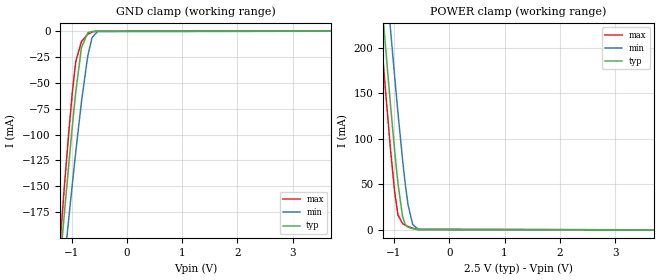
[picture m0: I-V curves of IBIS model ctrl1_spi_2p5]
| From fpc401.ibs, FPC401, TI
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|   ctrl1_spi_2p5 Model
[Model]   ctrl1_spi_2p5
Model_type   Input
Vinl = 0.75
Vinh = 1.75
|   typ   min   max
|   (nom PVT)   (fast PVT)   (slow PVT)
C_comp   3.323e-12   3.283e-12   3.373e-12
| Where nom  PVT is Nominal Process, 2.5V, 27C
|   Fast PVT is Strong Process,  2.65V, -40C
|   Slow PVT is Weak Process,   2.35V, 125C
[Voltage Range]   2.5   2.35   2.65
|Junction Temperature
[Temperature Range]   27   125   -40
[Power Clamp Reference]   2.5   2.35   2.65
[GND Clamp Reference]   0   0   0
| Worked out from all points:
|   GND clamp passes 1 mA (typ) near -0.67 V on its own axis
|   POWER clamp passes 1 mA (typ) near -0.63 V on its own axis
[GND Clamp]
|   Voltage   I(typ)   I(min)   I(max)
-2.5V     -1.076A    -999.1mA   -1.173A
-1.265V   -260.4mA   -296.2mA   -245.6mA
-1.133V   -178.4mA   -224.7mA   -152.9mA
-1.097V   -157mA     -205.9mA   -129mA
-1.052V   -130.5mA   -182.5mA   -99.78mA
-985mV    -91.97mA   -147.8mA   -58.97mA
-923.2mV  -58.98mA   -116.9mA   -29.3mA
-819.9mV  -15.92mA   -68.35mA   -10.12mA
-705.9mV  -1.65mA    -24.05mA   -3.017mA
-627.5mV  -378.3uA   -6.231mA   -803.9uA
-530.7mV  -48.81uA   -526.9uA   -88.92uA
5V        0A         0A         0A
[POWER Clamp]
|   Voltage   I(typ)   I(min)   I(max)
-2.5V     1.257A     1.315A     1.24A
-1.26V    279.7mA    361.8mA    232.8mA
-1.159V   205.3mA    288.3mA    156.9mA
-1.062V   136.2mA    219.1mA    87.67mA
-987.5mV  86.55mA    167.9mA    41.5mA
-928.5mV  51.09mA    128.7mA    16.6mA
-845.6mV  14.85mA    77.42mA    7.025mA
-793.9mV  5.674mA    49.25mA    5.223mA
-745.7mV  3.042mA    27.55mA    3.847mA
-662.3mV  1.416mA    6.079mA    1.934mA
-563.6mV  434.9uA    773.4uA    531.7uA
5V        0A         0A         0A
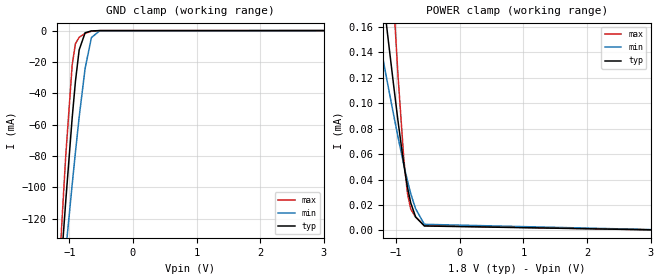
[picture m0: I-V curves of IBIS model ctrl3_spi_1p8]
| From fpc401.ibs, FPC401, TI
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|   ctrl3_spi_1p8 Model
[Model]   ctrl3_spi_1p8
Model_type   Input
Vinl = 0.54
Vinh = 1.26
|   typ   min   max
|   (nom PVT)   (fast PVT)   (slow PVT)
C_comp   1.078e-12   1.078e-12   1.078e-12
| Where nom  PVT is Nominal Process, 1.8V, 27C
|   Fast PVT is Strong Process,  1.95V, -40C
|   Slow PVT is Weak Process,   1.65V, 125C
[Voltage Range]   1.8   1.65   1.95
|Junction Temperature
[Temperature Range]   27   125   -40
[Power Clamp Reference]   1.8   1.65   1.95
[GND Clamp Reference]   0   0   0
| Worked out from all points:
|   GND clamp passes 1 mA (typ) near -0.73 V on its own axis
[GND Clamp]
|   Voltage   I(typ)   I(min)   I(max)
-1.8V     -556.9mA   -476.6mA   -661.8mA
-1.191V   -186.6mA   -199.8mA   -178.6mA
-1.147V   -160.7mA   -180.3mA   -145.3mA
-1.108V   -138.4mA   -163.3mA   -116.8mA
-1.055V   -108.6mA   -140.4mA   -79.7mA
-953.7mV  -55.51mA   -98.01mA   -21.81mA
-903mV    -32.44mA   -77.62mA   -8.4mA
-844.2mV  -12.32mA   -55.13mA   -4.254mA
-750.6mV  -1.393mA   -24.05mA   -1.808mA
-651.6mV  -214.4uA   -4.491mA   -445.5uA
-522.9mV  -14.93uA   -149.5uA   -26.3uA
3.6V      0A         0A         0A
[POWER Clamp]
|   Voltage   I(typ)   I(min)   I(max)
-1.8V     453.3uA    299uA      889.9uA
-1.401V   271.5uA    187.6uA    509.9uA
-1.256V   207.1uA    148.1uA    374.7uA
-1.135V   154.4uA    115.7uA    264.1uA
-1.041V   114.8uA    91.31uA    181.3uA
-969.3mV  85.51uA    73.08uA    120.8uA
-878.4mV  51.63uA    51.35uA    55.59uA
-822.6mV  34.16uA    39.13uA    29.31uA
-770.4mV  21.71uA    28.95uA    16.82uA
-694.8mV  10.77uA    17.16uA    10.5uA
-556.2mV  3.534uA    4.838uA    3.853uA
3.6V      0A         0A         0A
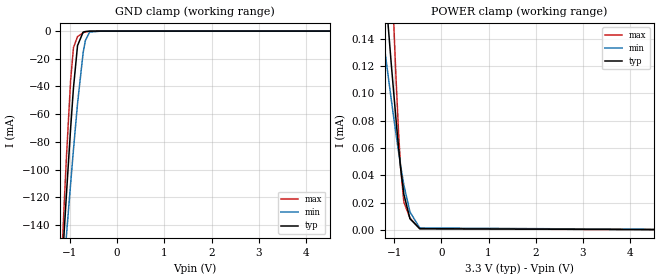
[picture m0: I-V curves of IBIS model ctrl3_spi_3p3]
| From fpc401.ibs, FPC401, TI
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|   ctrl3_spi_3p3 Model
[Model]   ctrl3_spi_3p3
Model_type   Input
Vinl = 0.99
Vinh = 2.31
|   typ   min   max
|   (nom PVT)   (fast PVT)   (slow PVT)
C_comp   1.079e-12   1.078e-12   1.087e-12
| Where nom  PVT is Nominal Process, 3.3V, 27C
|   Fast PVT is Strong Process,  3.6V, -40C
|   Slow PVT is Weak Process,   3V, 125C
[Voltage Range]   3.3   3   3.6
|Junction Temperature
[Temperature Range]   27   125   -40
[Power Clamp Reference]   3.3   3   3.6
[GND Clamp Reference]   0   0   0
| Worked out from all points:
|   GND clamp passes 1 mA (typ) near -0.73 V on its own axis
[GND Clamp]
|   Voltage   I(typ)   I(min)   I(max)
-3.3V     -1.497A    -1.178A    -1.889A
-1.197V   -189.1mA   -201.8mA   -181.8mA
-1.115V   -141.5mA   -165.7mA   -120.7mA
-1.076V   -119.5mA   -148.9mA   -92.97mA
-985.2mV  -70.57mA   -110.5mA   -35.84mA
-924mV    -40.87mA   -85.43mA   -11.9mA
-838.2mV  -10.51mA   -52.44mA   -3.986mA
-720mV    -732.9uA   -15.76mA   -1.234mA
-672mV    -304.1uA   -6.775mA   -613.8uA
-582mV    -52.5uA    -738.5uA   -104.3uA
-330mV    -89.36nA   -744.8nA   -56.52nA
6.6V      0A         0A         0A
[POWER Clamp]
|   Voltage   I(typ)   I(min)   I(max)
-3.3V     1.156mA    727.3uA    2.344mA
-1.251V   204.1uA    146.3uA    368.3uA
-1.2V     181.9uA    132.7uA    321.6uA
-1.082V   131.3uA    101.5uA    215.6uA
-1.061V   122.2uA    95.94uA    196.6uA
-960mV    81.27uA    70.45uA    112.1uA
-906mV    60.85uA    57.44uA    72.14uA
-862.8mV  45.91uA    47.53uA    45.99uA
-792mV    26uA       32.73uA    20.37uA
-663.3mV  8.201uA    13.21uA    8.723uA
-456mV    938.5nA    1.48uA     846.4nA
6.6V      0A         0A         0A
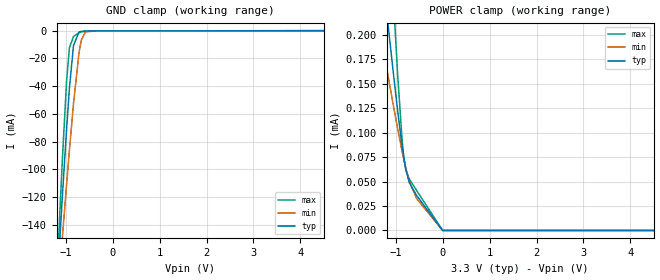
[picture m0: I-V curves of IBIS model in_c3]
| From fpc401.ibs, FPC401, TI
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|   in_c3 Model
[Model]   in_c3
Model_type   Input
Vinl = 0.8
Vinh = 2
|   typ   min   max
|   (nom PVT)   (fast PVT)   (slow PVT)
C_comp   1.056e-12   1.054e-12   1.064e-12
| Where nom  PVT is Nominal Process, 3.3V, 27C
|   Fast PVT is Strong Process,  3.6V, -40C
|   Slow PVT is Weak Process,   3V, 125C
[Voltage Range]   3.3   3   3.6
|Junction Temperature
[Temperature Range]   27   125   -40
[Power Clamp Reference]   3.3   3   3.6
[GND Clamp Reference]   0   0   0
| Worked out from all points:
|   GND clamp passes 1 mA (typ) near -0.72 V on its own axis
[GND Clamp]
|   Voltage   I(typ)   I(min)   I(max)
-3.3V     -1.497A    -1.178A    -1.889A
-1.197V   -189.4mA   -202mA     -182.1mA
-1.115V   -141.8mA   -166mA     -121mA
-1.076V   -119.7mA   -149.1mA   -93.29mA
-985.2mV  -70.83mA   -110.7mA   -36.16mA
-924mV    -41.13mA   -85.64mA   -12.21mA
-838.2mV  -10.77mA   -52.65mA   -4.3mA
-720mV    -986.9uA   -15.96mA   -1.546mA
-672mV    -556.6uA   -6.981mA   -923.9uA
-582mV    -301.4uA   -942.3uA   -410.8uA
-330mV    -233.9uA   -192uA     -289.6uA
6.6V      0A         0A         0A
[POWER Clamp]
|   Voltage   I(typ)   I(min)   I(max)
-3.3V     1.207mA    765.2uA    2.408mA
-1.37V    301.9uA    213.7uA    529.6uA
-1.188V   219.4uA    163.6uA    358.5uA
-1.056V   161.5uA    128.2uA    238.7uA
-960mV    121.3uA    103.4uA    157.2uA
-864.6mV  85.16uA    80.14uA    90.59uA
-826.8mV  72.99uA    71.6uA     73.26uA
-786mV    62.04uA    63.05uA    61.53uA
-715.2mV  48.87uA    50.4uA     52.66uA
-558mV    35.78uA    32.63uA    40.88uA
-3.3mV    0A         17.47nA    44.25nA
6.6V      0A         0A         0A
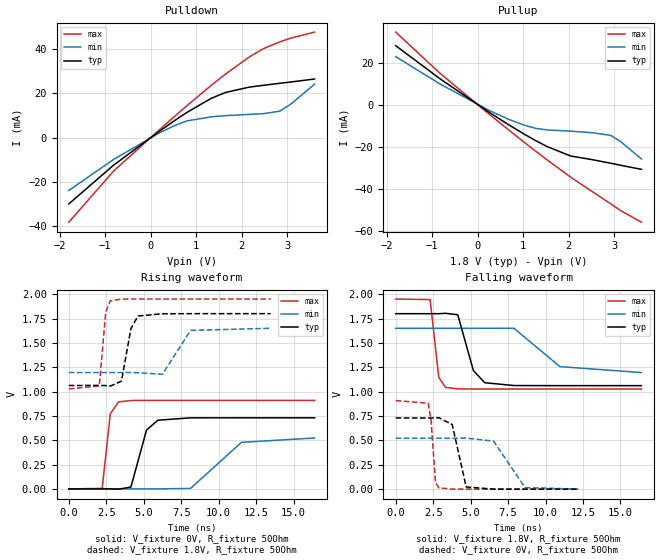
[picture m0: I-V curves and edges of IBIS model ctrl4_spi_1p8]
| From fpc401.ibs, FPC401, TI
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|   ctrl4_spi_1p8 Model
[Model]   ctrl4_spi_1p8
Model_type   Output
Polarity   Non-Inverting
Vmeas = 0.9
Vref = 0
Cref = 2pF
Rref =150
|   typ   min   max
|   (nom PVT)   (fast PVT)   (slow PVT)
C_comp   1.266e-14   1.230e-14   1.995e-14
| Where nom  PVT is Nominal Process, 1.8V, 27C
|   Fast PVT is Strong Process,  1.95V, -40C
|   Slow PVT is Weak Process,   1.65V, 125C
[Voltage Range]   1.8   1.65   1.95
|Junction Temperature
[Temperature Range]   27   125   -40
[Pullup Reference]   1.8   1.65   1.95
[Pulldown Reference]   0   0   0
[Power Clamp Reference]   1.8   1.65   1.95
[GND Clamp Reference]   0   0   0
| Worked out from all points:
|   slope of the pulldown table from 0 to 0.27 V, typ, clamps not added: 67.3 ohm
|   slope of the pullup table from 0 to 0.27 V, typ, clamps not added: 69.9 ohm
|   falling waveform, V_fixture 1.8V, R_fixture 50Ohm: 20-80 % time 784ps typ, 1.97ns min, 310ps max; typ from 1.8 V to 1.06 V
|   rising waveform, V_fixture 0V, R_fixture 50Ohm: 20-80 % time 722ps typ, 1.87ns min, 319ps max; typ from 0 V to 0.73 V
|   rising waveform, V_fixture 1.8V, R_fixture 50Ohm: 20-80 % time 468ps typ, 792ps min, 241ps max; typ from 1.06 V to 1.8 V
|   falling waveform, V_fixture 0V, R_fixture 50Ohm: 20-80 % time 510ps typ, 1.11ns min, 236ps max; typ from 0.73 V to 0 V
[Pulldown]
|   Voltage   I(typ)   I(min)   I(max)
-1.8V     -30.03mA   -23.95mA   -38.3mA
-817.2mV  -12.51mA   -9.904mA   -15.17mA
196.8mV   2.965mA    2.195mA    3.659mA
528.2mV   7.741mA    5.468mA    9.674mA
795.4mV   11.39mA    7.539mA    14.44mA
1.328V    17.75mA    9.395mA    23.6mA
1.649V    20.46mA    9.924mA    28.84mA
2.166V    22.83mA    10.5mA     36.51mA
2.482V    23.67mA    10.84mA    40.31mA
2.835V    24.57mA    11.94mA    43.31mA
3.089V    25.18mA    15.32mA    45.08mA
3.6V      26.51mA    24.19mA    47.74mA
[Pullup]
|   Voltage   I(typ)   I(min)   I(max)
-1.8V     28.02mA    22.83mA    34.49mA
-822.6mV  12.23mA    9.767mA    14.82mA
251mV     -3.622mA   -2.739mA   -4.498mA
671.7mV   -9.444mA   -6.899mA   -11.87mA
1.024V    -14.05mA   -9.784mA   -17.92mA
1.287V    -17.27mA   -11.33mA   -22.35mA
1.533V    -20.03mA   -12.06mA   -26.4mA
2.045V    -24.44mA   -12.63mA   -34.5mA
2.524V    -26.21mA   -13.38mA   -41.45mA
2.929V    -27.91mA   -14.69mA   -47.25mA
3.147V    -28.88mA   -17.66mA   -50.48mA
3.6V      -30.8mA    -25.87mA   -55.93mA
[Ramp]
R_load = 50
|   typ   min   max
dV/dt_r   0.438136/7.21814e-10   0.313826/1.87407e-09   0.545381/3.19219e-10
dV/dt_f   0.442539/7.83738e-10   0.273051/1.97718e-09   0.553614/3.09688e-10
[Falling Waveform]
V_fixture = 1.8V
V_fixture_min = 1.65V
V_fixture_max = 1.95V
R_fixture = 50Ohm
|   Time   V(typ)   V(min)   V(max)
0s        1.8V       1.65V      1.95V
2.294ns   1.8V       1.65V      1.945V
2.875ns   1.8V       1.65V      1.148V
3.319ns   1.804V     1.65V      1.044V
4.144ns   1.789V     1.65V      1.029V
5.185ns   1.217V     1.65V      1.027V
5.939ns   1.092V     1.651V     1.027V
7.886ns   1.063V     1.651V     1.027V
10.96ns   1.062V     1.257V     1.027V
16.4ns    1.062V     1.196V     1.027V
[Rising Waveform]
V_fixture = 0V
V_fixture_min = 0V
V_fixture_max = 0V
R_fixture = 50Ohm
|   Time   V(typ)   V(min)   V(max)
0s        523pV      20.8nV     260.9pV
2.227ns   90.6uV     12.08nV    5.005mV
2.767ns   259.2uV    10.87nV    771.4mV
3.319ns   -2.879mV   2.108uV    893.8mV
4.144ns   19.03mV    3.658uV    907.9mV
5.185ns   604.2mV    233.8uV    908.9mV
5.939ns   705.7mV    -162.1uV   909mV
8.124ns   729.8mV    5.132mV    909mV
11.52ns   730.2mV    478.2mV    909mV
16.4ns    730.2mV    522.8mV    909mV
[Rising Waveform]
V_fixture = 1.8V
V_fixture_min = 1.65V
V_fixture_max = 1.95V
R_fixture = 50Ohm
|   Time   V(typ)   V(min)   V(max)
0s        1.062V     1.195V     1.027V
2.033ns   1.063V     1.195V     1.058V
2.463ns   1.061V     1.195V     1.814V
2.767ns   1.056V     1.195V     1.933V
3.514ns   1.107V     1.195V     1.949V
4.144ns   1.646V     1.196V     1.95V
4.613ns   1.776V     1.193V     1.95V
6.242ns   1.799V     1.177V     1.95V
8.124ns   1.8V       1.628V     1.95V
13.47ns   1.8V       1.65V      1.95V
[Falling Waveform]
V_fixture = 0V
V_fixture_min = 0V
V_fixture_max = 0V
R_fixture = 50Ohm
|   Time   V(typ)   V(min)   V(max)
0s        730.2mV    523mV      909mV
2.168ns   730.1mV    523mV      881.3mV
2.355ns   730mV      523mV      713.7mV
2.657ns   731mV      523mV      70.24mV
2.875ns   732.7mV    523mV      13.61mV
3.771ns   662.9mV    522.8mV    299.2uV
4.705ns   22.74mV    523.5mV    12.73uV
6.531ns   304.9uV    493mV      1.942uV
8.628ns   9.883uV    16.63mV    -2.72uV
12.19ns   6.404uV    201uV      13.13uV
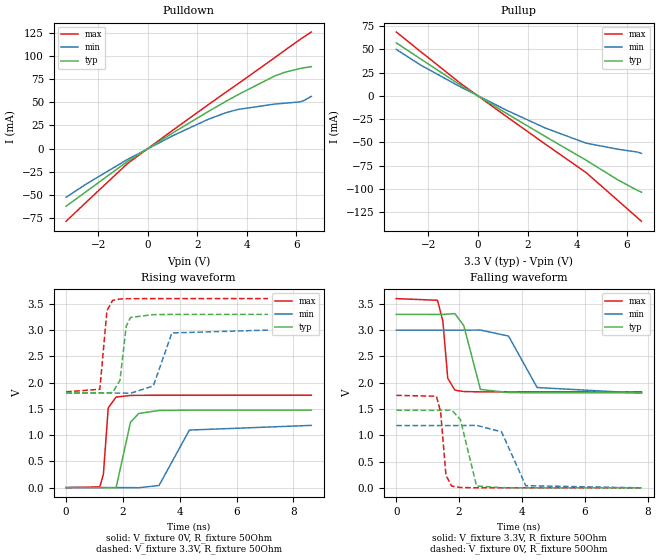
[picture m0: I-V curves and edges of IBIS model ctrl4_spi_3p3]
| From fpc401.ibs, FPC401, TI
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|   ctrl4_spi_3p3 Model
[Model]   ctrl4_spi_3p3
Model_type   Output
Polarity   Non-Inverting
Vmeas = 1.65
Vref = 0
Cref = 50pF
Rref = 100
|   typ   min   max
|   (nom PVT)   (fast PVT)   (slow PVT)
C_comp   1.230e-14   1.150e-14   1.962e-14
| Where nom  PVT is Nominal Process, 3.3V, 27C
|   Fast PVT is Strong Process,  3.6V, -40C
|   Slow PVT is Weak Process,   3V, 125C
[Voltage Range]   3.3   3   3.6
|Junction Temperature
[Temperature Range]   27   125   -40
[Pullup Reference]   3.3   3   3.6
[Pulldown Reference]   0   0   0
[Power Clamp Reference]   3.3   3   3.6
[GND Clamp Reference]   0   0   0
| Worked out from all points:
|   slope of the pulldown table from 0 to 0.495 V, typ, clamps not added: 59.6 ohm
|   slope of the pullup table from 0 to 0.495 V, typ, clamps not added: 61.1 ohm
|   falling waveform, V_fixture 3.3V, R_fixture 50Ohm: 20-80 % time 245ps typ, 505ps min, 153ps max; typ from 3.3 V to 1.81 V
|   rising waveform, V_fixture 0V, R_fixture 50Ohm: 20-80 % time 215ps typ, 511ps min, 127ps max; typ from 0 V to 1.48 V
|   rising waveform, V_fixture 3.3V, R_fixture 50Ohm: 20-80 % time 183ps typ, 339ps min, 124ps max; typ from 1.81 V to 3.3 V
|   falling waveform, V_fixture 0V, R_fixture 50Ohm: 20-80 % time 207ps typ, 367ps min, 137ps max; typ from 1.48 V to 0 V
[Pulldown]
|   Voltage   I(typ)   I(min)   I(max)
-3.3V     -62.26mA   -52.59mA   -78.49mA
-2.448V   -45.66mA   -37.66mA   -56.92mA
-822mV    -13.95mA   -11.79mA   -16.21mA
1.024V    17.12mA    14.05mA    20.07mA
2.436V    39.87mA    31.49mA    47.24mA
3.132V    50.59mA    38.48mA    60.38mA
3.63V     57.96mA    42.15mA    69.66mA
5.121V    78.27mA    47.97mA    98.01mA
5.554V    82.48mA    48.95mA    106.4mA
6.132V    86.26mA    50.27mA    117.4mA
6.316V    87.15mA    51.9mA     120.7mA
6.6V      88.32mA    56.28mA    125.7mA
[Pullup]
|   Voltage   I(typ)   I(min)   I(max)
-3.3V     57mA       49.97mA    68.61mA
-2.319V   39.75mA    33.18mA    47.64mA
-719.4mV  11.82mA    9.868mA    13.8mA
1.185V    -19.34mA   -15.77mA   -22.78mA
2.73V     -43.76mA   -34.6mA    -51.99mA
4.365V    -69.03mA   -50.72mA   -82.35mA
5.639V    -90.03mA   -57.17mA   -112.1mA
6.435V    -101.4mA   -60.27mA   -130.8mA
6.6V      -103.4mA   -61.66mA   -134.6mA
[Ramp]
R_load = 50
|   typ   min   max
dV/dt_r   0.88529/2.15442e-10   0.711024/5.10621e-10   1.05524/1.26841e-10
dV/dt_f   0.895288/2.4533e-10   0.719434/5.05804e-10   1.06478/1.53449e-10
[Falling Waveform]
V_fixture = 3.3V
V_fixture_min = 3V
V_fixture_max = 3.6V
R_fixture = 50Ohm
|   Time   V(typ)   V(min)   V(max)
0s        3.3V       3V         3.6V
1.313ns   3.299V     3V         3.568V
1.483ns   3.3V       3V         3.173V
1.639ns   3.305V     3V         2.085V
1.867ns   3.314V     3V         1.858V
2.15ns    3.085V     3V         1.832V
2.68ns    1.872V     3.002V     1.826V
3.576ns   1.812V     2.887V     1.825V
4.485ns   1.808V     1.908V     1.825V
7.808ns   1.808V     1.801V     1.825V
[Rising Waveform]
V_fixture = 0V
V_fixture_min = 0V
V_fixture_max = 0V
R_fixture = 50Ohm
|   Time   V(typ)   V(min)   V(max)
0s        657.7pV    14.65nV    458.6pV
1.188ns   507.5uV    36.28nV    16.22mV
1.313ns   422.5uV    1.028uV    253.9mV
1.483ns   -2.868mV   -3.276uV   1.52V
1.759ns   -4.429mV   20.3uV     1.724V
2.268ns   1.249V     354.1uV    1.756V
2.557ns   1.412V     -2.515mV   1.758V
3.271ns   1.469V     40.75mV    1.759V
4.338ns   1.475V     1.096V     1.759V
8.627ns   1.475V     1.185V     1.759V
[Rising Waveform]
V_fixture = 3.3V
V_fixture_min = 3V
V_fixture_max = 3.6V
R_fixture = 50Ohm
|   Time   V(typ)   V(min)   V(max)
0s        1.808V     1.801V     1.825V
1.188ns   1.808V     1.801V     1.873V
1.437ns   1.804V     1.801V     3.37V
1.639ns   1.812V     1.801V     3.567V
1.895ns   2.043V     1.801V     3.592V
2.117ns   3.075V     1.799V     3.598V
2.268ns   3.241V     1.797V     3.599V
3.069ns   3.295V     1.937V     3.6V
3.722ns   3.299V     2.946V     3.6V
7.105ns   3.3V       3V         3.6V
[Falling Waveform]
V_fixture = 0V
V_fixture_min = 0V
V_fixture_max = 0V
R_fixture = 50Ohm
|   Time   V(typ)   V(min)   V(max)
0s        1.476V     1.185V     1.759V
1.276ns   1.475V     1.185V     1.743V
1.412ns   1.476V     1.185V     1.448V
1.582ns   1.479V     1.185V     237.8mV
1.764ns   1.481V     1.185V     33mV
2.041ns   1.3V       1.185V     6.609mV
2.557ns   34.91mV    1.188V     531.1uV
3.351ns   3.222mV    1.066V     7.724uV
4.124ns   512.3uV    40.55mV    20.25uV
7.808ns   -13.34uV   266.7uV    -48.42uV
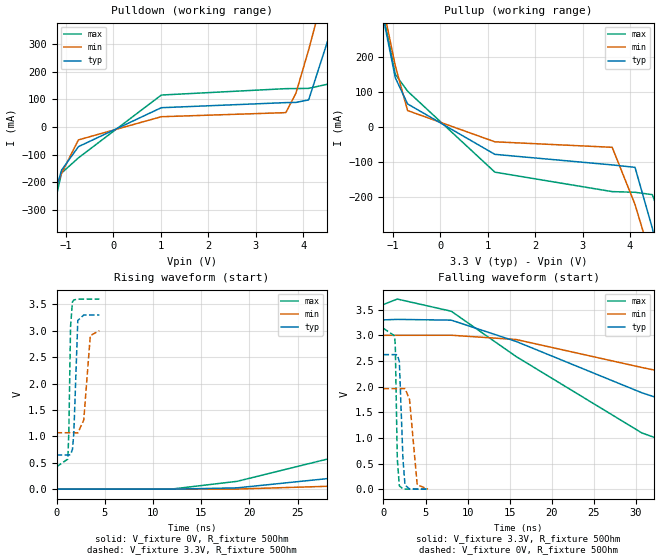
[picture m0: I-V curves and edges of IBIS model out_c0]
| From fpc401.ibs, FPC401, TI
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|   out_c0 Model
[Model]   out_c0
Model_type   Output
Polarity   Non-Inverting
Vmeas = 1.65
Vref = 0
Cref = 2pF
Rref = 50
|   typ   min   max
|   (nom PVT)   (fast PVT)   (slow PVT)
C_comp   1.546e-12   1.546e-12   1.585e-12
| Where nom  PVT is Nominal Process, 3.3V, 27C
|   Fast PVT is Strong Process,  3.6V, -40C
|   Slow PVT is Weak Process,   3V, 125C
[Voltage Range]   3.3   3   3.6
|Junction Temperature
[Temperature Range]   27   125   -40
[Pullup Reference]   3.3   3   3.6
[Pulldown Reference]   0   0   0
[Power Clamp Reference]   3.3   3   3.6
[GND Clamp Reference]   0   0   0
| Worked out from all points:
|   slope of the pulldown table from 0 to 0.495 V, typ, clamps not added: 11.5 ohm
|   slope of the pullup table from 0 to 0.495 V, typ, clamps not added: 12.3 ohm
|   falling waveform, V_fixture 3.3V, R_fixture 50Ohm: 20-80 % time 29.1ns typ, 46.7ns min, 18.8ns max; typ from 3.3 V to 0.647 V
|   rising waveform, V_fixture 0V, R_fixture 50Ohm: 20-80 % time 65ns typ, 109ns min, 41.7ns max; typ from 0 V to 2.62 V
|   rising waveform, V_fixture 3.3V, R_fixture 50Ohm: 20-80 % time 247ps typ, 440ps min, 167ps max; typ from 0.646 V to 3.3 V
|   falling waveform, V_fixture 0V, R_fixture 50Ohm: 20-80 % time 296ps typ, 534ps min, 199ps max; typ from 2.62 V to 0.001 V
[Pulldown]
|   Voltage   I(typ)   I(min)   I(max)
-3.3V     -1.522A    -1.189A    -1.938A
-1.702V   -515.2mA   -439.4mA   -620mA
-1.093V   -155.1mA   -166.7mA   -165.8mA
-738mV    -70.56mA   -46.09mA   -111mA
1.009V    70.28mA    37.69mA    116.1mA
3.634V    88.69mA    52.45mA    139.2mA
3.846V    89.36mA    122mA      139.5mA
4.116V    98.59mA    279.7mA    140.2mA
4.516V    311.6mA    537.4mA    155.3mA
4.811V    507.9mA    734mA      319.2mA
5.214V    785.2mA    1.007A     597.6mA
6.596V    1.77A      1.966A     1.609A
[Pullup]
|   Voltage   I(typ)   I(min)   I(max)
-3.3V     1.854A     1.824A     1.914A
-1.356V   418.8mA    443.8mA    433.6mA
-1.236V   333mA      362.2mA    343.5mA
-949.2mV  140.7mA    174.7mA    150.4mA
-690mV    66.05mA    47.16mA    102.3mA
1.15V     -77.44mA   -41.75mA   -128.1mA
3.623V    -107.5mA   -57.4mA    -183.5mA
4.105V    -114.4mA   -220.1mA   -185.4mA
4.47V     -287.5mA   -384.1mA   -192.1mA
4.62V     -377.1mA   -453mA     -247.5mA
4.811V    -493.8mA   -541.4mA   -386.2mA
6.6V      -1.619A    -1.383A    -1.847A
[Ramp]
R_load = 50
|   typ   min   max
dV/dt_r   1.57366/6.50991e-08   1.17602/1.0963e-07   1.88137/4.1683e-08
dV/dt_f   1.59227/2.91431e-08   1.15963/4.68647e-08   1.90616/1.87859e-08
[Falling Waveform]
V_fixture = 3.3V
V_fixture_min = 3V
V_fixture_max = 3.6V
R_fixture = 50Ohm
|   Time   V(typ)   V(min)   V(max)
0s        3.3V       3V         3.6V
1.65ns    3.31V      3V         3.706V
8.058ns   3.295V     3.001V     3.469V
15.79ns   2.878V     2.917V     2.583V
30.7ns    1.879V     2.372V     1.096V
35.02ns   1.648V     2.227V     845.3mV
46.45ns   1.177V     1.898V     589.6mV
66.09ns   826.8mV    1.518V     483.3mV
100ns     695.5mV    1.221V     438mV
246.9ns   646.7mV    1.07V      423.1mV
[Rising Waveform]
V_fixture = 0V
V_fixture_min = 0V
V_fixture_max = 0V
R_fixture = 50Ohm
|   Time   V(typ)   V(min)   V(max)
0s        424.2pV    23.37nV    77.27pV
12.08ns   -519.4uV   -566.5uV   4.642mV
18.72ns   24.33mV    1.955mV    147.9mV
31.84ns   269.7mV    74.31mV    738.8mV
57.04ns   970.2mV    397.8mV    1.99V
76.64ns   1.493V     672.9mV    2.668V
100ns     2V         974.3mV    2.904V
146.3ns   2.394V     1.429V     3.041V
226.9ns   2.548V     1.787V     3.107V
606.9ns   2.622V     1.955V     3.135V
[Rising Waveform]
V_fixture = 3.3V
V_fixture_min = 3V
V_fixture_max = 3.6V
R_fixture = 50Ohm
|   Time   V(typ)   V(min)   V(max)
0s        646.2mV    1.068V     423.1mV
1.172ns   646.3mV    1.068V     569.1mV
1.274ns   645.4mV    1.068V     1.07V
1.454ns   654.9mV    1.068V     3.079V
1.65ns    751.9mV    1.068V     3.545V
1.794ns   1.062V     1.068V     3.584V
2.206ns   3.194V     1.065V     3.596V
2.821ns   3.297V     1.307V     3.598V
3.503ns   3.299V     2.909V     3.599V
4.444ns   3.299V     2.999V     3.599V
[Falling Waveform]
V_fixture = 0V
V_fixture_min = 0V
V_fixture_max = 0V
R_fixture = 50Ohm
|   Time   V(typ)   V(min)   V(max)
0s        2.623V     1.96V      3.136V
1.346ns   2.623V     1.96V      2.987V
1.418ns   2.624V     1.96V      2.744V
1.65ns    2.62V      1.96V      592mV
1.893ns   2.489V     1.96V      65.76mV
2.323ns   584.2mV    1.961V     5.255mV
2.565ns   81.5mV     1.963V     2.721mV
3.103ns   5.184mV    1.748V     1.995mV
4.013ns   980.7uV    86.89mV    1.299mV
5.295ns   1.25mV     1.695mV    1.259mV
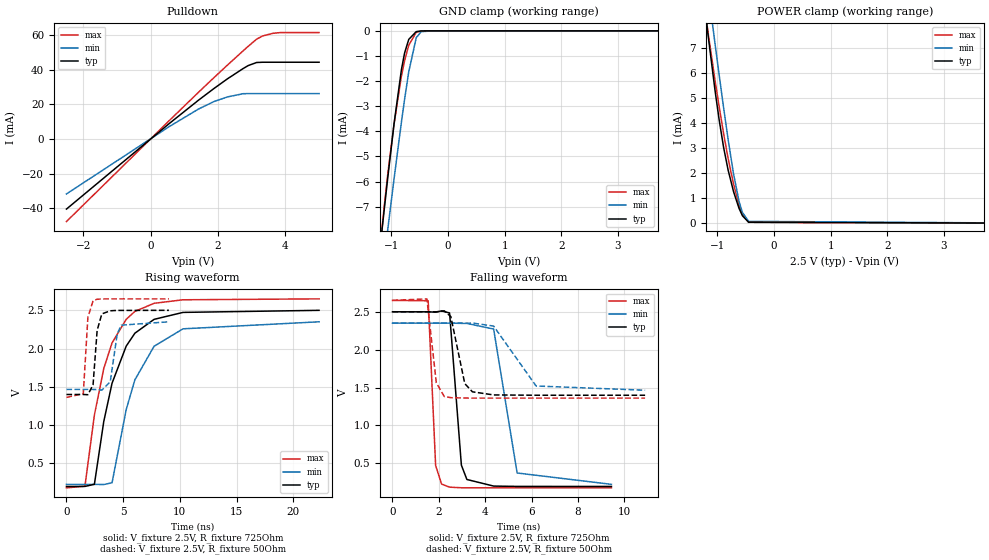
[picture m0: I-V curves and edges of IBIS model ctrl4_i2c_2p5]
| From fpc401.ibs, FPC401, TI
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|   ctrl4_i2c_2p5 Model
[Model]   ctrl4_i2c_2p5
Model_type   I/O_open_drain
Polarity   Non-Inverting
Vinl = 0.8
Vinh = 2
Vmeas = 1.25
Vref = 2.5
Cref = 50pF
Rref = 725
|   typ   min   max
|   (nom PVT)   (fast PVT)   (slow PVT)
C_comp   1.310e-14   1.206e-14   2.058e-14
| Where nom  PVT is Nominal Process, 2.5V, 27C
|   Fast PVT is Strong Process,  2.65V, -40C
|   Slow PVT is Weak Process,   2.35V, 125C
[Voltage Range]   2.5   2.35   2.65
|Junction Temperature
[Temperature Range]   27   125   -40
[Pullup Reference]   2.5   2.35   2.65
[Pulldown Reference]   0   0   0
[Power Clamp Reference]   2.5   2.35   2.65
[GND Clamp Reference]   0   0   0
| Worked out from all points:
|   slope of the pulldown table from 0 to 0.375 V, typ, clamps not added: 61.9 ohm
|   GND clamp passes 1 mA (typ) near -0.78 V on its own axis
|   POWER clamp passes 1 mA (typ) near -0.68 V on its own axis
|   falling waveform, V_fixture 2.5V, R_fixture 725Ohm: 20-80 % time 294ps typ, 549ps min, 180ps max; typ from 2.5 V to 0.196 V
|   rising waveform, V_fixture 2.5V, R_fixture 725Ohm: 20-80 % time 2.41ns typ, 2.59ns min, 2.24ns max; typ from 0.196 V to 2.5 V
|   falling waveform, V_fixture 2.5V, R_fixture 50Ohm: 20-80 % time 423ps typ, 962ps min, 224ps max; typ from 2.5 V to 1.4 V
|   rising waveform, V_fixture 2.5V, R_fixture 50Ohm: 20-80 % time 335ps typ, 495ps min, 275ps max; typ from 1.4 V to 2.5 V
[Pulldown]
|   Voltage   I(typ)   I(min)   I(max)
-2.5V     -40.36mA   -31.64mA   -47.55mA
559.7mV   9.048mA    7.265mA    10.76mA
1.42V     22.37mA    17.26mA    26.92mA
1.88V     29.12mA    21.6mA     35.38mA
2.282V    34.71mA    24.27mA    42.64mA
2.745V    40.6mA     26.11mA    50.8mA
2.898V    42.34mA    26.17mA    53.45mA
3.145V    44.09mA    26.17mA    57.51mA
3.32V     44.24mA    26.17mA    59.35mA
3.622V    44.24mA    26.17mA    60.89mA
3.849V    44.24mA    26.17mA    61.33mA
5V        44.24mA    26.17mA    61.33mA
[GND Clamp]
|   Voltage   I(typ)   I(min)   I(max)
-2.5V     -37.1mA    -35.65mA   -43.25mA
-1.215V   -9.013mA   -10.77mA   -9.073mA
-1.127V   -7.203mA   -9.137mA   -7.084mA
-1.06V    -5.838mA   -7.894mA   -5.697mA
-949.7mV  -3.703mA   -5.895mA   -3.714mA
-820mV    -1.553mA   -3.642mA   -1.807mA
-764.2mV  -886.6uA   -2.733mA   -1.194mA
-690.1mV  -339.4uA   -1.626mA   -573.7uA
-557.5mV  -31.05uA   -270.3uA   -57.36uA
-469.6mV  -4.145uA   -32.73uA   -6.158uA
-248.7mV  0A         -92.86nA   0A
5V        0A         0A         0A
[POWER Clamp]
|   Voltage   I(typ)   I(min)   I(max)
-2.5V     34.48mA    34mA       37.75mA
-1.175V   7.756mA    9.56mA     7.836mA
-1.147V   7.245mA    9.073mA    7.384mA
-1.035V   5.236mA    7.095mA    5.646mA
-965mV    4.112mA    5.904mA    4.64mA
-887.5mV  3.027mA    4.613mA    3.577mA
-807.5mV  2.121mA    3.341mA    2.58mA
-712.5mV  1.266mA    1.972mA    1.568mA
-615.9mV  600uA      877.3uA    729.1uA
-555mV    300.7uA    431uA      344.3uA
-446.1mV  43.48uA    78.16uA    37.03uA
5V        0A         0A         0A
[Ramp]
R_load = 725
|   typ   min   max
dV/dt_r   1.38242/2.40689e-09   1.27618/2.58765e-09   1.48345/2.24003e-09
dV/dt_f   1.38242/2.93791e-10   1.27617/5.49634e-10   1.48343/1.79819e-10
[Falling Waveform]
V_fixture = 2.5V
V_fixture_min = 2.35V
V_fixture_max = 2.65V
R_fixture = 725Ohm
|   Time   V(typ)   V(min)   V(max)
0s        2.5V       2.35V      2.65V
1.541ns   2.499V     2.35V      2.645V
1.862ns   2.495V     2.35V      471.6mV
2.12ns    2.511V     2.35V      227.1mV
2.464ns   2.484V     2.35V      186.7mV
2.973ns   476.8mV    2.347V     178.7mV
3.211ns   287.9mV    2.346V     178.1mV
4.365ns   200.8mV    2.272V     177.6mV
5.379ns   196.5mV    373.5mV    177.6mV
9.448ns   195.9mV    223.8mV    177.6mV
[Rising Waveform]
V_fixture = 2.5V
V_fixture_min = 2.35V
V_fixture_max = 2.65V
R_fixture = 725Ohm
|   Time   V(typ)   V(min)   V(max)
0s        195.9mV    223mV      177.6mV
1.629ns   196.3mV    223mV      199mV
2.464ns   223.9mV    223.3mV    1.13V
3.289ns   1.044V     220.8mV    1.738V
4.022ns   1.547V     244.3mV    2.074V
5.27ns    2.032V     1.202V     2.383V
6.037ns   2.201V     1.591V     2.486V
7.73ns    2.382V     2.03V      2.592V
10.28ns   2.473V     2.258V     2.638V
22.28ns   2.5V       2.35V      2.65V
[Falling Waveform]
V_fixture = 2.5V
V_fixture_min = 2.35V
V_fixture_max = 2.65V
R_fixture = 50Ohm
|   Time   V(typ)   V(min)   V(max)
0s        2.5V       2.35V      2.65V
1.485ns   2.5V       2.35V      2.67V
1.891ns   2.499V     2.35V      1.564V
2.237ns   2.512V     2.35V      1.382V
2.518ns   2.436V     2.35V      1.367V
3.12ns    1.552V     2.349V     1.362V
3.45ns    1.444V     2.351V     1.361V
4.365ns   1.403V     2.311V     1.361V
6.196ns   1.399V     1.521V     1.361V
10.9ns    1.399V     1.465V     1.361V
[Rising Waveform]
V_fixture = 2.5V
V_fixture_min = 2.35V
V_fixture_max = 2.65V
R_fixture = 50Ohm
|   Time   V(typ)   V(min)   V(max)
0s        1.399V     1.465V     1.361V
1.485ns   1.399V     1.465V     1.41V
1.891ns   1.396V     1.465V     2.41V
2.347ns   1.526V     1.465V     2.625V
2.707ns   2.238V     1.463V     2.645V
3.12ns    2.453V     1.456V     2.649V
3.862ns   2.494V     1.564V     2.65V
4.474ns   2.499V     2.19V      2.65V
4.827ns   2.499V     2.306V     2.65V
9.036ns   2.5V       2.35V      2.65V
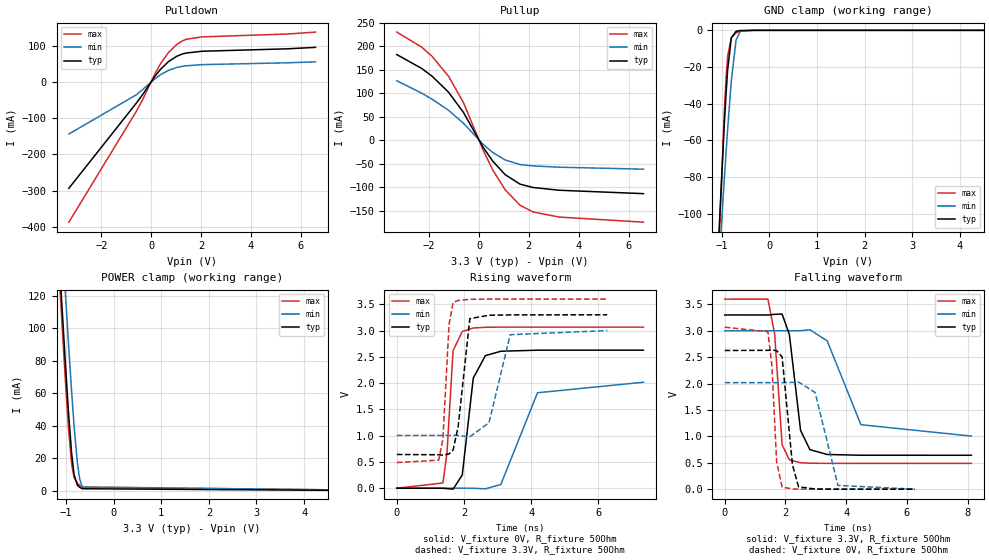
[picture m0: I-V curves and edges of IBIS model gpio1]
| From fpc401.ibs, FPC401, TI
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|   gpio1 Model
[Model]   gpio1
Model_type   I/O
Polarity   Non-Inverting
Enable   Active-Low
Vinl = 0.8
Vinh = 2
Vmeas = 1.65
Vref = 3.3
Cref = 2pF
Rref = 50
|   typ   min   max
|   (nom PVT)   (fast PVT)   (slow PVT)
C_comp   1.404e-12   1.404e-12   1.437e-12
| Where nom  PVT is Nominal Process, 3.3V, 25C
|   Fast PVT is Strong Process,  3.6V, 0C
|   Slow PVT is Weak Process,   3V, 100C
[Voltage Range]   3.3   3   3.6
|Junction Temperature
[Temperature Range]   25   100   0
[Pullup Reference]   3.3   3   3.6
[Pulldown Reference]   0   0   0
[Power Clamp Reference]   3.3   3   3.6
[GND Clamp Reference]   0   0   0
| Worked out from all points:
|   slope of the pulldown table from 0 to 0.495 V, typ, clamps not added: 11.4 ohm
|   slope of the pullup table from 0 to 0.495 V, typ, clamps not added: 12.2 ohm
|   GND clamp passes 1 mA (typ) near -0.73 V on its own axis
|   POWER clamp passes 1 mA (typ) near -0.63 V on its own axis
|   falling waveform, V_fixture 3.3V, R_fixture 50Ohm: 20-80 % time 303ps typ, 673ps min, 204ps max; typ from 3.3 V to 0.642 V
|   rising waveform, V_fixture 0V, R_fixture 50Ohm: 20-80 % time 273ps typ, 644ps min, 158ps max; typ from 0 V to 2.63 V
|   rising waveform, V_fixture 3.3V, R_fixture 50Ohm: 20-80 % time 201ps typ, 371ps min, 149ps max; typ from 0.642 V to 3.3 V
|   falling waveform, V_fixture 0V, R_fixture 50Ohm: 20-80 % time 212ps typ, 391ps min, 159ps max; typ from 2.63 V to 0 V
[Pulldown]
|   Voltage   I(typ)   I(min)   I(max)
-3.3V     -293.6mA   -143.5mA   -387.3mA
-588mV    -57.71mA   -35mA      -80.27mA
-330mV    -33.6mA    -20.06mA   -47.39mA
153mV     15.91mA    9.171mA    22.91mA
378mV     35.35mA    20.37mA    50.84mA
696mV     56.43mA    32.34mA    81.43mA
1.027V    71.32mA    40.38mA    103.7mA
1.251V    77.6mA     43.55mA    113.7mA
1.416V    80.42mA    45.08mA    118.3mA
2.042V    85.23mA    48.22mA    124.9mA
5.478V    91.98mA    53.36mA    132.9mA
6.6V      96.01mA    55.94mA    138.2mA
[GND Clamp]
|   Voltage   I(typ)   I(min)   I(max)
-3.3V     -1.496A    -1.164A    -1.92A
-1.194V   -185.9mA   -185.5mA   -214.6mA
-1.093V   -127.8mA   -141.5mA   -139.6mA
-1.076V   -118.1mA   -134mA     -127.1mA
-949.2mV  -51.31mA   -81.21mA   -44.27mA
-909.6mV  -33.41mA   -65.58mA   -24.79mA
-877.8mV  -21.14mA   -53.51mA   -13.79mA
-801.9mV  -4.158mA   -27.51mA   -3.968mA
-702mV    -502.7uA   -5.31mA    -1.43mA
-612mV    -92.88uA   -473.4uA   -417.6uA
-330mV    -81.23nA   -182.1nA   -493nA
6.6V      0A         0A         0A
[Pullup]
|   Voltage   I(typ)   I(min)   I(max)
-3.3V     182.3mA    126.6mA    230.2mA
-2.297V   152.7mA    99.94mA    198mA
-1.881V   136.1mA    87.21mA    178.4mA
-1.219V   102mA      63.46mA    135.8mA
-620.4mV  58.72mA    35.93mA    79.59mA
159.6mV   -14.57mA   -8.551mA   -20.51mA
551.1mV   -44.77mA   -26.12mA   -63.43mA
1.053V    -73.61mA   -42.26mA   -105.9mA
1.647V    -93.72mA   -52.04mA   -138.6mA
2.166V    -100.8mA   -54.79mA   -153mA
3.227V    -106.7mA   -57.61mA   -163.8mA
6.6V      -113.9mA   -61.77mA   -174.7mA
[POWER Clamp]
|   Voltage   I(typ)   I(min)   I(max)
-3.3V     1.38A      1.385A     1.401A
-1.288V   218.9mA    261.1mA    210.4mA
-1.14V    140.9mA    184.5mA    130.9mA
-1.101V   120.9mA    164.7mA    110.6mA
-1.01V    76.29mA    119.8mA    65.67mA
-951mV    49.29mA    91.48mA    39.32mA
-884.4mV  23.57mA    61.55mA    16.76mA
-831.6mV  10.01mA    40.04mA    8.187mA
-762mV    3.5mA      17.17mA    4.763mA
-714mV    2.211mA    7.333mA    3.505mA
-660mV    1.355mA    2.398mA    2.352mA
6.6V      0A         0A         0A
[Ramp]
R_load = 50
|   typ   min   max
dV/dt_r   1.57655/2.7281e-10   1.21054/6.44386e-10   1.83998/1.57656e-10
dV/dt_f   1.59479/3.02628e-10   1.19733/6.72964e-10   1.86675/2.03902e-10
[Falling Waveform]
V_fixture = 3.3V
V_fixture_min = 3V
V_fixture_max = 3.6V
R_fixture = 50Ohm
|   Time   V(typ)   V(min)   V(max)
0s        3.3V       3V         3.6V
1.422ns   3.299V     3V         3.601V
1.645ns   3.311V     3V         2.937V
1.89ns    3.317V     3V         840.4mV
2.129ns   2.93V      2.999V     554.4mV
2.497ns   1.115V     3.002V     500.2mV
2.804ns   748.8mV    3.02V      491.6mV
3.374ns   657.2mV    2.809V     488.8mV
4.484ns   642.5mV    1.221V     488.5mV
8.122ns   642.1mV    1.005V     488.6mV
[Rising Waveform]
V_fixture = 0V
V_fixture_min = 0V
V_fixture_max = 0V
R_fixture = 50Ohm
|   Time   V(typ)   V(min)   V(max)
0s        397.5pV    6.332nV    418.2pV
1.372ns   -1.202mV   6.013uV    99.33mV
1.494ns   -6.591mV   -62.43uV   669.4mV
1.675ns   -18.08mV   55.9uV     2.619V
1.948ns   251.2mV    947uV      2.982V
2.276ns   2.096V     -1.176mV   3.049V
2.637ns   2.524V     -12.01mV   3.063V
3.096ns   2.607V     70.99mV    3.066V
4.187ns   2.627V     1.817V     3.066V
7.341ns   2.627V     2.017V     3.066V
[Rising Waveform]
V_fixture = 3.3V
V_fixture_min = 3V
V_fixture_max = 3.6V
R_fixture = 50Ohm
|   Time   V(typ)   V(min)   V(max)
0s        642.1mV    1.005V     488.6mV
1.248ns   636.6mV    1.005V     533.9mV
1.372ns   629.2mV    1.005V     934.2mV
1.555ns   652.9mV    1.005V     3.113V
1.675ns   726.5mV    1.006V     3.535V
1.826ns   1.17V      1.004V     3.574V
2.174ns   3.228V     978.9mV    3.595V
2.746ns   3.292V     1.248V     3.6V
3.374ns   3.299V     2.922V     3.6V
6.262ns   3.3V       3V         3.6V
[Falling Waveform]
V_fixture = 0V
V_fixture_min = 0V
V_fixture_max = 0V
R_fixture = 50Ohm
|   Time   V(typ)   V(min)   V(max)
0s        2.627V     2.018V     3.067V
1.422ns   2.63V      2.018V     2.983V
1.555ns   2.635V     2.018V     2.337V
1.709ns   2.626V     2.017V     520.7mV
1.89ns    2.505V     2.017V     38.17mV
2.23ns    460.3mV    2.022V     3.413mV
2.432ns   45.51mV    2.029V     1.099mV
2.977ns   2.623mV    1.831V     -109.5uV
3.729ns   351.5uV    70.76mV    38.61uV
6.262ns   157.5uV    -79.63uV   133.8uV
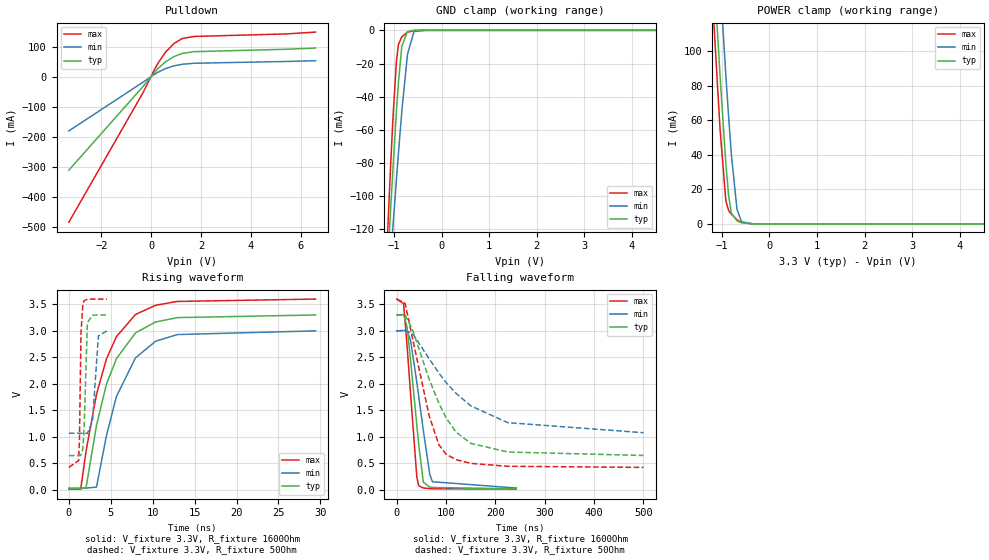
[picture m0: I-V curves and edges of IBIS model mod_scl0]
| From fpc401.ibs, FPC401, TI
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|   mod_scl0 Model
[Model]   mod_scl0
Model_type   I/O_open_drain
Polarity   Non-Inverting
Vinl = 1
Vinh = 2.2
Vmeas = 1.65
Vref = 3.3
Cref = 200pF
Rref = 1600
|   typ   min   max
|   (nom PVT)   (fast PVT)   (slow PVT)
C_comp   1.404e-12   1.371e-12   1.472e-12
| Where nom  PVT is Nominal Process, 3.3V, 27C
|   Fast PVT is Strong Process,  3.6V, -40C
|   Slow PVT is Weak Process,   3V, 125C
[Voltage Range]   3.3   3   3.6
|Junction Temperature
[Temperature Range]   27   125   -40
[Pullup Reference]   3.3   3   3.6
[Pulldown Reference]   0   0   0
[Power Clamp Reference]   3.3   3   3.6
[GND Clamp Reference]   0   0   0
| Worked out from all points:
|   slope of the pulldown table from 0 to 0.495 V, typ, clamps not added: 11.5 ohm
|   GND clamp passes 1 mA (typ) near -0.73 V on its own axis
|   POWER clamp passes 1 mA (typ) near -0.62 V on its own axis
|   falling waveform, V_fixture 3.3V, R_fixture 1600Ohm: 20-80 % time 20.7ns typ, 26.2ns min, 17ns max; typ from 3.3 V to 0.02 V
|   rising waveform, V_fixture 3.3V, R_fixture 1600Ohm: 20-80 % time 3.55ns typ, 3.55ns min, 3.59ns max; typ from 0.019 V to 3.3 V
|   falling waveform, V_fixture 3.3V, R_fixture 50Ohm: 20-80 % time 72ns typ, 115ns min, 46.6ns max; typ from 3.3 V to 0.648 V
|   rising waveform, V_fixture 3.3V, R_fixture 50Ohm: 20-80 % time 253ps typ, 446ps min, 175ps max; typ from 0.646 V to 3.3 V
[Pulldown]
|   Voltage   I(typ)   I(min)   I(max)
-3.3V     -311.4mA   -180.6mA   -484.6mA
-330mV    -33.39mA   -18.81mA   -54.18mA
108mV     11.47mA    6.203mA    19.2mA
282mV     27.36mA    14.84mA    45.57mA
580.8mV   49.31mA    26.71mA    81.67mA
922.8mV   66.96mA    36.02mA    110.7mA
1.251V    77.19mA    41.11mA    126.9mA
1.723V    83.06mA    44.51mA    133.8mA
5.426V    91.13mA    50.52mA    142.2mA
6.6V      95.17mA    52.92mA    148.3mA
[GND Clamp]
|   Voltage   I(typ)   I(min)   I(max)
-3.3V     -1.371A    -1.102A    -1.688A
-1.197V   -174.4mA   -189.4mA   -164.6mA
-1.111V   -129mA     -154.3mA   -107.7mA
-1.073V   -109mA     -138.6mA   -83.2mA
-1.021V   -83.21mA   -118.2mA   -52.74mA
-948mV    -48.8mA    -89.75mA   -18.42mA
-906mV    -31.32mA   -73.97mA   -8.542mA
-834.9mV  -9.545mA   -48.67mA   -3.877mA
-717mV    -692.6uA   -14.58mA   -1.187mA
-579mV    -49.3uA    -678.8uA   -97.43uA
-330mV    -89.41nA   -747.1nA   -56.52nA
6.6V      0A         0A         0A
[POWER Clamp]
|   Voltage   I(typ)   I(min)   I(max)
-3.3V     1.287A     1.299A     1.305A
-1.295V   209.6mA    262.4mA    181.5mA
-1.158V   142.2mA    196.3mA    111.8mA
-1.098V   113.5mA    168mA      82.58mA
-1.036V   84.59mA    139mA      53.85mA
-916.8mV  34.87mA    86.14mA    13.38mA
-858mV    16.25mA    61.76mA    7.733mA
-801.9mV  6.387mA    40.47mA    5.615mA
-683.1mV  1.805mA    8.507mA    2.452mA
-588mV    663.9uA    1.288mA    837.5uA
-330mV    2.634uA    8.717uA    1.261uA
6.6V      0A         0A         0A
[Ramp]
R_load = 1600
|   typ   min   max
dV/dt_r   1.96849/3.55189e-09   1.78069/3.54981e-09   2.15251/3.59165e-09
dV/dt_f   1.96847/2.06854e-08   1.78064/2.62167e-08   2.1525/1.69554e-08
[Falling Waveform]
V_fixture = 3.3V
V_fixture_min = 3V
V_fixture_max = 3.6V
R_fixture = 1600Ohm
|   Time   V(typ)   V(min)   V(max)
0s        3.3V       3V         3.6V
13.77ns   3.309V     3.009V     3.514V
20.81ns   3.073V     2.995V     2.721V
27.91ns   2.445V     2.823V     1.814V
40.61ns   1.224V     2.032V     242.4mV
44.5ns    854.2mV    1.764V     76.56mV
53.8ns    142.1mV    1.121V     35.16mV
66.95ns   52.63mV    289.8mV    23.24mV
72.2ns    44.34mV    153mV      21.16mV
242.1ns   19.97mV    34.52mV    12.75mV
[Rising Waveform]
V_fixture = 3.3V
V_fixture_min = 3V
V_fixture_max = 3.6V
R_fixture = 1600Ohm
|   Time   V(typ)   V(min)   V(max)
0s        19.18mV    32.18mV    12.49mV
1.409ns   17.49mV    32.18mV    13.55mV
2.058ns   45.62mV    32.56mV    736.7mV
3.297ns   1.219V     51.9mV     1.804V
4.477ns   1.99V      1.019V     2.468V
5.676ns   2.475V     1.762V     2.891V
7.948ns   2.962V     2.49V      3.309V
10.35ns   3.168V     2.805V     3.484V
12.94ns   3.25V      2.93V      3.555V
29.43ns   3.3V       3V         3.6V
[Falling Waveform]
V_fixture = 3.3V
V_fixture_min = 3V
V_fixture_max = 3.6V
R_fixture = 50Ohm
|   Time   V(typ)   V(min)   V(max)
0s        3.3V       3V         3.6V
16.98ns   3.296V     3V         3.518V
31.74ns   3.026V     2.956V     2.865V
65.37ns   2.093V     2.478V     1.408V
85.37ns   1.632V     2.202V     849.1mV
100ns     1.357V     2.025V     671.9mV
120ns     1.091V     1.822V     569.6mV
150ns     876.6mV    1.585V     499.3mV
224.7ns   714.4mV    1.268V     444.3mV
500ns     648.3mV    1.078V     423.4mV
[Rising Waveform]
V_fixture = 3.3V
V_fixture_min = 3V
V_fixture_max = 3.6V
R_fixture = 50Ohm
|   Time   V(typ)   V(min)   V(max)
0s        646.2mV    1.068V     423.1mV
1.164ns   646.2mV    1.068V     553.3mV
1.263ns   645.4mV    1.068V     949.7mV
1.446ns   653.1mV    1.068V     2.95V
1.669ns   770.6mV    1.068V     3.513V
1.821ns   1.169V     1.068V     3.571V
2.21ns    3.156V     1.065V     3.597V
2.818ns   3.296V     1.3V       3.6V
3.522ns   3.299V     2.905V     3.6V
4.527ns   3.3V       2.999V     3.6V
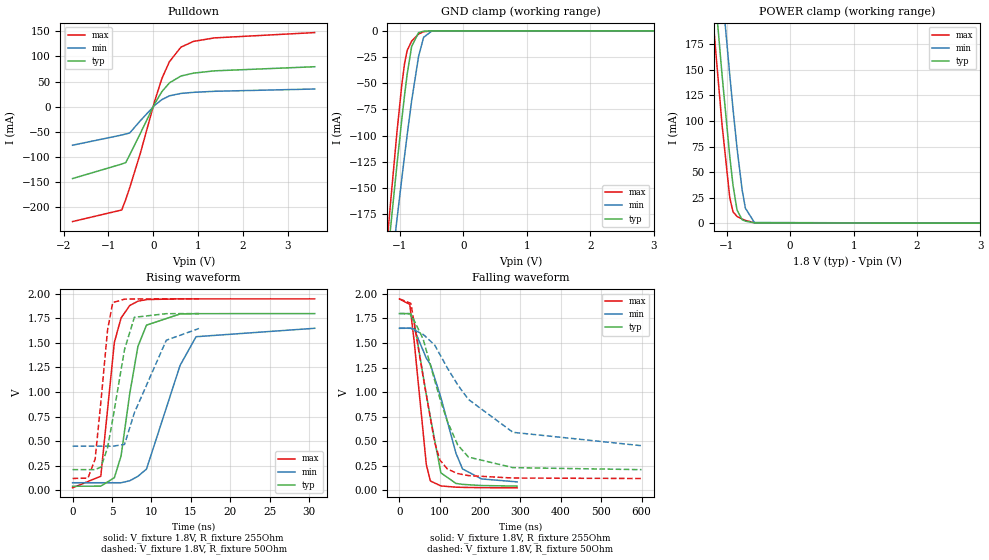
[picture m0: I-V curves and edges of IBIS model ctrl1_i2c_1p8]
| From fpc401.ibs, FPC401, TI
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|   ctrl1_i2c_1p8 Model
[Model]   ctrl1_i2c_1p8
Model_type   I/O_open_drain
Polarity   Non-Inverting
Vinl = 0.54
Vinh = 1.26
Vmeas = 0.9
Vref = 1.8
Cref = 550pF
Rref = 255
|   typ   min   max
|   (nom PVT)   (fast PVT)   (slow PVT)
C_comp   3.478e-12   3.353e-12   3.751e-12
| Where nom  PVT is Nominal Process, 1.8V, 27C
|   Fast PVT is Strong Process,  1.95V, -40C
|   Slow PVT is Weak Process,   1.65V, 125C
[Voltage Range]   1.8   1.65   1.95
|Junction Temperature
[Temperature Range]   27   125   -40
[Pullup Reference]   1.8   1.65   1.95
[Pulldown Reference]   0   0   0
[Power Clamp Reference]   1.8   1.65   1.95
[GND Clamp Reference]   0   0   0
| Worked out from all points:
|   slope of the pulldown table from 0 to 0.27 V, typ, clamps not added: 6.97 ohm
|   GND clamp passes 1 mA (typ) near -0.67 V on its own axis
|   POWER clamp passes 1 mA (typ) near -0.63 V on its own axis
|   falling waveform, V_fixture 1.8V, R_fixture 255Ohm: 20-80 % time 44.2ns typ, 70.6ns min, 27.2ns max; typ from 1.8 V to 0.041 V
|   rising waveform, V_fixture 1.8V, R_fixture 255Ohm: 20-80 % time 2.01ns typ, 3.6ns min, 1.46ns max; typ from 0.039 V to 1.8 V
|   falling waveform, V_fixture 1.8V, R_fixture 50Ohm: 20-80 % time 73ns typ, 136ns min, 44.6ns max; typ from 1.8 V to 0.208 V
|   rising waveform, V_fixture 1.8V, R_fixture 50Ohm: 20-80 % time 2.02ns typ, 3.51ns min, 1.22ns max; typ from 0.208 V to 1.8 V
[Pulldown]
|   Voltage   I(typ)   I(min)   I(max)
-1.8V     -142.9mA   -76.56mA   -228.5mA
-702mV    -114mA     -56.26mA   -205.4mA
-613.7mV  -111.1mA   -54.25mA   -184.5mA
-526.2mV  -95.99mA   -52.27mA   -161.4mA
-288.8mV  -53.16mA   -27.85mA   -92.72mA
34.95mV   6.582mA    3.147mA    12.29mA
192.9mV   30.17mA    14.22mA    56.4mA
361.5mV   47.6mA     21.79mA    89.9mA
617.2mV   61.15mA    26.53mA    118.6mA
897.8mV   66.92mA    28.67mA    130.1mA
1.361V    71.43mA    30.74mA    137mA
3.6V      79.63mA    35.3mA     147.6mA
[GND Clamp]
|   Voltage   I(typ)   I(min)   I(max)
-1.8V     -607.7mA   -595.9mA   -640.8mA
-1.191V   -214.8mA   -256.5mA   -193.9mA
-1.151V   -189.9mA   -234.7mA   -165.8mA
-1.048V   -128.1mA   -180.3mA   -97.16mA
-971.2mV  -84.77mA   -141.2mA   -51.83mA
-926.4mV  -60.99mA   -118.8mA   -30.81mA
-885.6mV  -41.21mA   -99.01mA   -18.64mA
-815.4mV  -14.86mA   -66.67mA   -9.798mA
-706mV    -1.675mA   -24.3mA    -3.051mA
-626.9mV  -378.7uA   -6.237mA   -804.6uA
-499.8mV  -24.3uA    -228.5uA   -40.78uA
3.6V      0A         0A         0A
[POWER Clamp]
|   Voltage   I(typ)   I(min)   I(max)
-1.8V     697.6mA    770.2mA    663mA
-1.409V   393mA      472.9mA    349.1mA
-1.208V   241.5mA    324.2mA    193.7mA
-1.17V    213.8mA    296.7mA    165.4mA
-1.073V   144.3mA    227.3mA    95.64mA
-952.2mV  65.14mA    144.7mA    24.89mA
-901.1mV  37.02mA    111.6mA    11.21mA
-838mV    13.02mA    73.48mA    6.749mA
-757.8mV  3.491mA    32.76mA    4.193mA
-706mV    2.119mA    14.73mA    2.878mA
-563.7mV  440.1uA    785.5uA    538.9uA
3.6V      0A         0A         0A
[Ramp]
R_load = 255
|   typ   min   max
dV/dt_r   1.05682/2.00869e-09   0.945242/3.60396e-09   1.15656/1.46053e-09
dV/dt_f   1.05655/4.42773e-08   0.943845/7.07863e-08   1.15648/2.72519e-08
[Falling Waveform]
V_fixture = 1.8V
V_fixture_min = 1.65V
V_fixture_max = 1.95V
R_fixture = 255Ohm
|   Time   V(typ)   V(min)   V(max)
0s        1.8V       1.65V      1.95V
25.8ns    1.8V       1.652V     1.893V
36.45ns   1.72V      1.644V     1.526V
66.79ns   973.3mV    1.345V     260mV
76.83ns   742.5mV    1.282V     93.13mV
102.9ns   175.7mV    943.5mV    42.59mV
140.2ns   68.1mV     375.7mV    30.07mV
156.5ns   58.46mV    216mV      27.9mV
203.6ns   46.71mV    113.8mV    24.79mV
291.6ns   40.75mV    84.12mV    23.02mV
[Rising Waveform]
V_fixture = 1.8V
V_fixture_min = 1.65V
V_fixture_max = 1.95V
R_fixture = 255Ohm
|   Time   V(typ)   V(min)   V(max)
0s        38.63mV    74.6mV     22.41mV
3.584ns   40.02mV    74.59mV    140.9mV
5.305ns   126.3mV    74.6mV     1.507V
6.156ns   348.1mV    74.4mV     1.755V
7.248ns   979.7mV    94.54mV    1.882V
8.291ns   1.465V     140.2mV    1.926V
9.381ns   1.682V     214mV      1.943V
13.64ns   1.796V     1.271V     1.95V
15.67ns   1.799V     1.564V     1.95V
30.72ns   1.8V       1.65V      1.95V
[Falling Waveform]
V_fixture = 1.8V
V_fixture_min = 1.65V
V_fixture_max = 1.95V
R_fixture = 50Ohm
|   Time   V(typ)   V(min)   V(max)
0s        1.8V       1.65V      1.95V
28.56ns   1.798V     1.65V      1.904V
58.9ns    1.54V      1.588V     1.155V
87.52ns   1.118V     1.479V     482.9mV
100.7ns   930mV      1.381V     305.5mV
119.2ns   698.4mV    1.244V     214mV
144.5ns   461.3mV    1.073V     168.9mV
171.2ns   336.6mV    924.2mV    147.7mV
281.5ns   229.1mV    589.1mV    123.1mV
600ns     208.5mV    452.8mV    118.2mV
[Rising Waveform]
V_fixture = 1.8V
V_fixture_min = 1.65V
V_fixture_max = 1.95V
R_fixture = 50Ohm
|   Time   V(typ)   V(min)   V(max)
0s        208.1mV    447.3mV    118.1mV
1.954ns   208.1mV    447.3mV    121.8mV
2.866ns   207.8mV    447.3mV    316.8mV
3.608ns   235.5mV    447.3mV    911.1mV
4.438ns   430.3mV    447.4mV    1.631V
5.098ns   723.5mV    447.1mV    1.912V
6.597ns   1.435V     465.4mV    1.947V
7.844ns   1.762V     788.3mV    1.949V
11.89ns   1.799V     1.528V     1.95V
16.04ns   1.8V       1.648V     1.95V
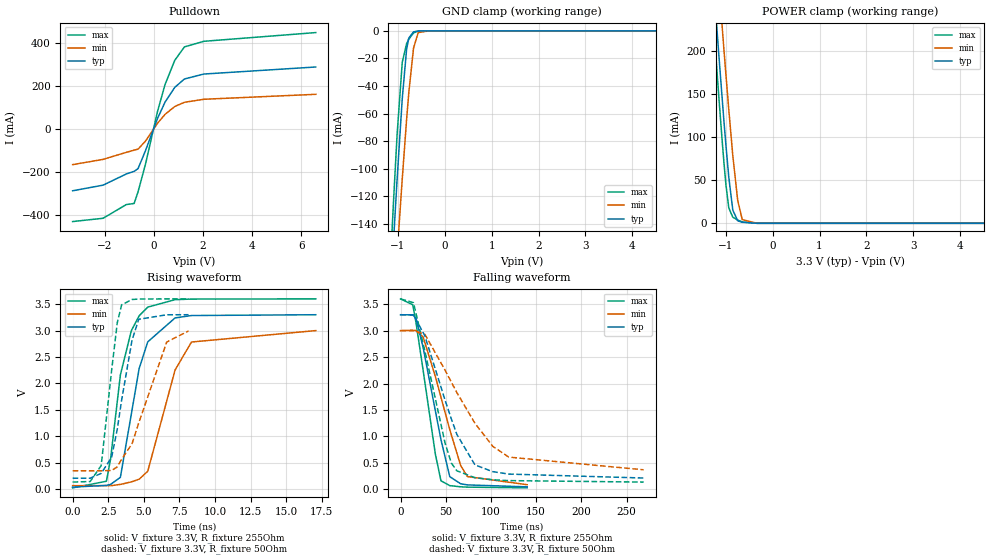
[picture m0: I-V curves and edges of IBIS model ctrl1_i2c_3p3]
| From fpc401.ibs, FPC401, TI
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|   ctrl1_i2c_3p3 Model
[Model]   ctrl1_i2c_3p3
Model_type   I/O_open_drain
Polarity   Non-Inverting
Vinl = 0.99
Vinh = 2.31
Vmeas = 1.65
Vref = 3.3
Cref = 550pF
Rref = 255
|   typ   min   max
|   (nom PVT)   (fast PVT)   (slow PVT)
C_comp   3.122e-12   3.015e-12   3.353e-12
| Where nom  PVT is Nominal Process, 3.3V, 27C
|   Fast PVT is Strong Process,  3.6V, -40C
|   Slow PVT is Weak Process,   3V, 125C
[Voltage Range]   3.3   3   3.6
|Junction Temperature
[Temperature Range]   27   125   -40
[Pullup Reference]   3.3   3   3.6
[Pulldown Reference]   0   0   0
[Power Clamp Reference]   3.3   3   3.6
[GND Clamp Reference]   0   0   0
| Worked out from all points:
|   slope of the pulldown table from 0 to 0.495 V, typ, clamps not added: 3.82 ohm
|   GND clamp passes 1 mA (typ) near -0.68 V on its own axis
|   POWER clamp passes 1 mA (typ) near -0.63 V on its own axis
|   falling waveform, V_fixture 3.3V, R_fixture 255Ohm: 20-80 % time 22.2ns typ, 28.4ns min, 18.3ns max; typ from 3.3 V to 0.048 V
|   rising waveform, V_fixture 3.3V, R_fixture 255Ohm: 20-80 % time 1.32ns typ, 1.71ns min, 1.24ns max; typ from 0.04 V to 3.3 V
|   falling waveform, V_fixture 3.3V, R_fixture 50Ohm: 20-80 % time 36.2ns typ, 54.9ns min, 26.6ns max; typ from 3.3 V to 0.215 V
|   rising waveform, V_fixture 3.3V, R_fixture 50Ohm: 20-80 % time 1.13ns typ, 1.88ns min, 780ps max; typ from 0.208 V to 3.3 V
[Pulldown]
|   Voltage   I(typ)   I(min)   I(max)
-3.3V     -287.6mA   -166.2mA   -430.5mA
-2.059V   -261.4mA   -141.7mA   -415.2mA
-1.115V   -209.6mA   -109.1mA   -351.6mA
-795.3mV  -197.3mA   -98.78mA   -346.4mA
-636mV    -184.6mA   -94.31mA   -292.3mA
-330mV    -100.2mA   -56.42mA   -162.5mA
153mV     47.43mA    25.68mA    79.28mA
462mV     124.1mA    67.27mA    205.9mA
858mV     192.6mA    103.8mA    318.3mA
1.251V    231.6mA    123.3mA    380.6mA
2.042V    254.6mA    137.4mA    406.6mA
6.597V    287.3mA    160.4mA    447.1mA
[GND Clamp]
|   Voltage   I(typ)   I(min)   I(max)
-3.3V     -1.62A     -1.468A    -1.788A
-1.266V   -260.5mA   -296.3mA   -245.6mA
-1.122V   -171.5mA   -218.7mA   -145.1mA
-1.083V   -148.1mA   -198.1mA   -119mA
-1.014V   -107.8mA   -162.3mA   -75.29mA
-904.2mV  -49.22mA   -107.3mA   -22.79mA
-811.8mV  -13.51mA   -64.5mA    -9.369mA
-765.6mV  -5.255mA   -45.18mA   -6.088mA
-663.3mV  -739.7uA   -12.46mA   -1.535mA
-564mV    -100.1uA   -1.281mA   -195.5uA
-330mV    -250.3nA   -2.129uA   -158.7nA
6.597V    0A         0A         0A
[POWER Clamp]
|   Voltage   I(typ)   I(min)   I(max)
-3.3V     1.909A     1.948A     1.91A
-1.267V   284.5mA    366.7mA    237.6mA
-1.147V   196.1mA    279.3mA    147.4mA
-1.083V   150.4mA    233.6mA    101.5mA
-1.036V   117.7mA    200.4mA    69.75mA
-993.3mV  89.76mA    171.4mA    44.17mA
-933.9mV  53.64mA    131.8mA    17.86mA
-848.1mV  15.33mA    78.5mA     7.091mA
-744mV    2.966mA    26.64mA    3.777mA
-646.8mV  1.205mA    4.293mA    1.631mA
-330mV    2.194uA    7.269uA    1.05uA
6.597V    0A         0A         0A
[Ramp]
R_load = 255
|   typ   min   max
dV/dt_r   1.95588/1.31585e-09   1.75954/1.70933e-09   2.1443/1.23684e-09
dV/dt_f   1.95418/2.22493e-08   1.7549/2.84934e-08   2.14364/1.82987e-08
[Falling Waveform]
V_fixture = 3.3V
V_fixture_min = 3V
V_fixture_max = 3.6V
R_fixture = 255Ohm
|   Time   V(typ)   V(min)   V(max)
0s        3.3V       3V         3.6V
13.53ns   3.298V     3.005V     3.488V
17.18ns   3.228V     3.001V     3.143V
25.03ns   2.678V     2.876V     2.246V
38.5ns    1.486V     2.135V     666.5mV
44.72ns   939.5mV    1.74V      161.7mV
54.44ns   240.4mV    1.129V     71.45mV
66.51ns   106.1mV    451.5mV    48.73mV
73.91ns   85.11mV    242.7mV    42.76mV
140ns     48.01mV    88.63mV    29.3mV
[Rising Waveform]
V_fixture = 3.3V
V_fixture_min = 3V
V_fixture_max = 3.6V
R_fixture = 255Ohm
|   Time   V(typ)   V(min)   V(max)
0s        40.2mV     67.43mV    26.17mV
2.372ns   72.45mV    67.53mV    150.9mV
2.662ns   90.04mV    66.3mV     564.5mV
3.354ns   225.6mV    91.07mV    2.162V
4.123ns   1.422V     138.9mV    2.998V
4.672ns   2.283V     190mV      3.28V
5.276ns   2.787V     340.1mV    3.444V
7.194ns   3.24V      2.255V     3.585V
8.346ns   3.285V     2.784V     3.596V
17.07ns   3.3V       3V         3.6V
[Falling Waveform]
V_fixture = 3.3V
V_fixture_min = 3V
V_fixture_max = 3.6V
R_fixture = 50Ohm
|   Time   V(typ)   V(min)   V(max)
0s        3.3V       3V         3.6V
14.3ns    3.297V     3.001V     3.528V
26.88ns   2.902V     2.932V     2.619V
49.2ns    1.689V     2.255V     878.2mV
56.17ns   1.331V     2.025V     496.9mV
62.32ns   1.038V     1.828V     351.3mV
82.31ns   462.7mV    1.248V     220.5mV
102ns     335.3mV    813.7mV    181.9mV
119.6ns   289.5mV    610.5mV    166mV
268.8ns   214.9mV    370mV      138mV
[Rising Waveform]
V_fixture = 3.3V
V_fixture_min = 3V
V_fixture_max = 3.6V
R_fixture = 50Ohm
|   Time   V(typ)   V(min)   V(max)
0s        208.2mV    348.7mV    135.6mV
1.232ns   208.2mV    348.7mV    145.6mV
2.007ns   299.8mV    348.8mV    448mV
2.741ns   605.6mV    353.8mV    2.252V
3.133ns   1.131V     423.5mV    3.145V
3.441ns   1.683V     567.1mV    3.487V
4.169ns   2.815V     857.9mV    3.588V
4.641ns   3.214V     1.252V     3.596V
6.608ns   3.299V     2.784V     3.6V
8.139ns   3.3V       2.993V     3.6V
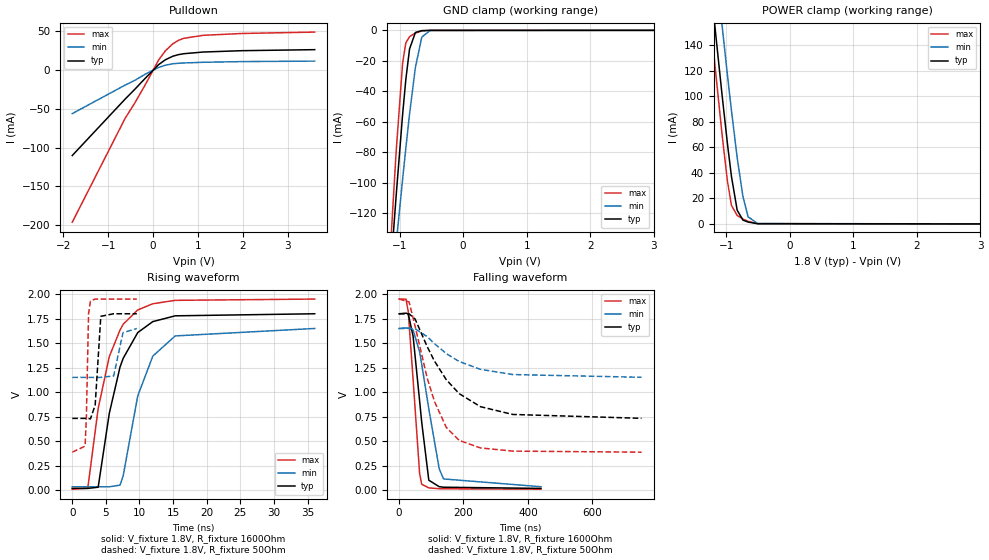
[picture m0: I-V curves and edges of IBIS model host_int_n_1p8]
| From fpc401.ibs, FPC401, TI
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|   host_int_n_1p8 Model
[Model]   host_int_n_1p8
Model_type   I/O_open_drain
Polarity   Non-Inverting
Vinl = 0.8
Vinh = 2
Vmeas = 0.9
Vref = 1.8
Cref = 2pF
Rref = 1600
|   typ   min   max
|   (nom PVT)   (fast PVT)   (slow PVT)
C_comp   1.546e-12   1.508e-12   1.625e-12
| Where nom  PVT is Nominal Process, 1.8V, 27C
|   Fast PVT is Strong Process,  1.95V, -40C
|   Slow PVT is Weak Process,   1.65V, 125C
[Voltage Range]   1.8   1.65   1.95
|Junction Temperature
[Temperature Range]   27   125   -40
[Pullup Reference]   1.8   1.65   1.95
[Pulldown Reference]   0   0   0
[Power Clamp Reference]   1.8   1.65   1.95
[GND Clamp Reference]   0   0   0
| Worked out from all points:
|   slope of the pulldown table from 0 to 0.27 V, typ, clamps not added: 20.9 ohm
|   GND clamp passes 1 mA (typ) near -0.73 V on its own axis
|   POWER clamp passes 1 mA (typ) near -0.62 V on its own axis
|   falling waveform, V_fixture 1.8V, R_fixture 1600Ohm: 20-80 % time 32.4ns typ, 48.5ns min, 24ns max; typ from 1.8 V to 0.018 V
|   rising waveform, V_fixture 1.8V, R_fixture 1600Ohm: 20-80 % time 3.55ns typ, 3.62ns min, 3.55ns max; typ from 0.018 V to 1.8 V
|   falling waveform, V_fixture 1.8V, R_fixture 50Ohm: 20-80 % time 130ns typ, 141ns min, 84.6ns max; typ from 1.8 V to 0.733 V
|   rising waveform, V_fixture 1.8V, R_fixture 50Ohm: 20-80 % time 463ps typ, 756ps min, 272ps max; typ from 0.733 V to 1.8 V
[Pulldown]
|   Voltage   I(typ)   I(min)   I(max)
-1.8V     -110.3mA   -56.28mA   -196.3mA
-620.2mV  -37.4mA    -19.42mA   -62.07mA
-413.5mV  -25.3mA    -13.59mA   -43.23mA
-180mV    -11.03mA   -5.628mA   -19.63mA
124.6mV   6.963mA    3.308mA    12.99mA
274.8mV   13.19mA    6.141mA    24.76mA
435.8mV   17.66mA    7.945mA    33.58mA
563.4mV   19.78mA    8.647mA    38.16mA
682.2mV   20.97mA    9.046mA    40.82mA
1.113V    23.14mA    9.924mA    44.69mA
1.98V     24.89mA    10.82mA    47.08mA
3.6V      26.21mA    11.45mA    48.87mA
[GND Clamp]
|   Voltage   I(typ)   I(min)   I(max)
-1.8V     -555.9mA   -475.6mA   -660.9mA
-1.191V   -186.2mA   -199.4mA   -178.2mA
-1.147V   -160.4mA   -179.9mA   -145mA
-1.108V   -138.1mA   -162.9mA   -116.5mA
-1.055V   -108.4mA   -140.1mA   -79.45mA
-953.7mV  -55.35mA   -97.75mA   -21.63mA
-903mV    -32.31mA   -77.4mA    -8.252mA
-844.2mV  -12.23mA   -54.96mA   -4.142mA
-752.4mV  -1.404mA   -24.46mA   -1.781mA
-651.6mV  -200.9uA   -4.45mA    -424.1uA
-522.9mV  -13.7uA    -145.3uA   -24.56uA
3.6V      0A         0A         0A
[POWER Clamp]
|   Voltage   I(typ)   I(min)   I(max)
-1.8V     471.6mA    515.8mA    454.6mA
-1.414V   270.7mA    321.6mA    245mA
-1.211V   168.8mA    222.4mA    139.3mA
-1.17V    148.7mA    202.7mA    118.6mA
-1.067V   99.85mA    154.3mA    68.93mA
-984.9mV  62.84mA    116.6mA    33.56mA
-921.6mV  37.19mA    88.78mA    14.56mA
-831.5mV  10.75mA    51.9mA     6.66mA
-741.1mV  3.042mA    21.47mA    3.874mA
-659.9mV  1.479mA    5.602mA    1.994mA
-509.7mV  199.7uA    318.4uA    208.5uA
3.6V      0A         0A         0A
[Ramp]
R_load = 1600
|   typ   min   max
dV/dt_r   1.06899/3.55178e-09   0.968898/3.62312e-09   1.1636/3.55329e-09
dV/dt_f   1.06898/3.23983e-08   0.968933/4.85435e-08   1.16359/2.40006e-08
[Falling Waveform]
V_fixture = 1.8V
V_fixture_min = 1.65V
V_fixture_max = 1.95V
R_fixture = 1600Ohm
|   Time   V(typ)   V(min)   V(max)
0s        1.8V       1.65V      1.95V
21.54ns   1.806V     1.655V     1.949V
28.48ns   1.799V     1.654V     1.821V
43.5ns    1.571V     1.635V     1.131V
63.7ns    913.4mV    1.411V     171.3mV
70.18ns   695.7mV    1.287V     61.28mV
92.31ns   101.9mV    829.4mV    23.61mV
124.6ns   36.13mV    219mV      15.55mV
138.2ns   30.54mV    114.9mV    14.29mV
440.6ns   18.47mV    35.69mV    10.7mV
[Rising Waveform]
V_fixture = 1.8V
V_fixture_min = 1.65V
V_fixture_max = 1.95V
R_fixture = 1600Ohm
|   Time   V(typ)   V(min)   V(max)
0s        18.35mV    35.17mV    10.67mV
2.306ns   18.49mV    35.17mV    20.5mV
3.853ns   30.71mV    35.16mV    834.1mV
5.511ns   785.4mV    35mV       1.364V
7.108ns   1.258V     51.71mV    1.635V
7.585ns   1.347V     151.2mV    1.694V
9.738ns   1.608V     961.9mV    1.839V
11.98ns   1.72V      1.368V     1.902V
15.31ns   1.779V     1.574V     1.937V
36.06ns   1.8V       1.65V      1.95V
[Falling Waveform]
V_fixture = 1.8V
V_fixture_min = 1.65V
V_fixture_max = 1.95V
R_fixture = 50Ohm
|   Time   V(typ)   V(min)   V(max)
0s        1.8V       1.65V      1.95V
31.18ns   1.799V     1.65V      1.92V
49.79ns   1.746V     1.647V     1.672V
87.13ns   1.466V     1.567V     1.146V
109.6ns   1.319V     1.496V     907.4mV
146.5ns   1.128V     1.394V     641.4mV
186.5ns   985.4mV    1.313V     508.5mV
252.9ns   851.9mV    1.233V     431.3mV
352.9ns   772.9mV    1.18V      399mV
752.9ns   733.4mV    1.152V     388mV
[Rising Waveform]
V_fixture = 1.8V
V_fixture_min = 1.65V
V_fixture_max = 1.95V
R_fixture = 50Ohm
|   Time   V(typ)   V(min)   V(max)
0s        732.8mV    1.151V     387.9mV
1.903ns   732.8mV    1.151V     449.5mV
2.094ns   733mV      1.151V     737.9mV
2.423ns   731.6mV    1.151V     1.801V
2.698ns   727.3mV    1.151V     1.93V
3.407ns   868.4mV    1.151V     1.95V
4.244ns   1.774V     1.151V     1.95V
6.155ns   1.8V       1.166V     1.95V
7.542ns   1.8V       1.607V     1.95V
9.605ns   1.8V       1.65V      1.95V
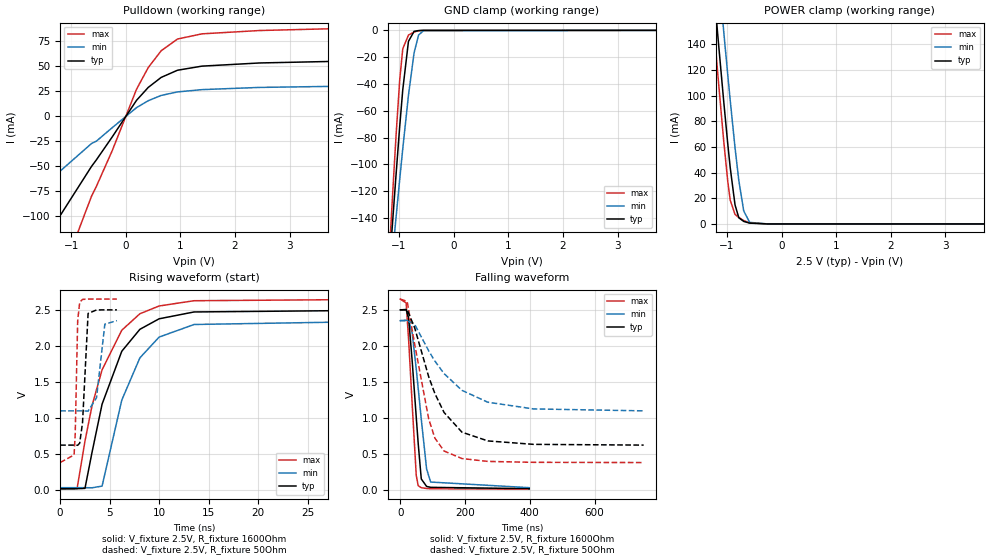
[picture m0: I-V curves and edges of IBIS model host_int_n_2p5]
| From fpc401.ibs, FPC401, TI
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|   host_int_n_2p5 Model
[Model]   host_int_n_2p5
Model_type   I/O_open_drain
Polarity   Non-Inverting
Vinl = 0.8
Vinh = 2
Vmeas = 1.25
Vref = 2.5
Cref = 2pF
Rref = 1600
|   typ   min   max
|   (nom PVT)   (fast PVT)   (slow PVT)
C_comp   1.472e-12   1.437e-12   1.508e-12
| Where nom  PVT is Nominal Process, 2.5V, 27C
|   Fast PVT is Strong Process,  2.65V, -40C
|   Slow PVT is Weak Process,   2.35V, 125C
[Voltage Range]   2.5   2.35   2.65
|Junction Temperature
[Temperature Range]   27   125   -40
[Pullup Reference]   2.5   2.35   2.65
[Pulldown Reference]   0   0   0
[Power Clamp Reference]   2.5   2.35   2.65
[GND Clamp Reference]   0   0   0
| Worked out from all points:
|   slope of the pulldown table from 0 to 0.375 V, typ, clamps not added: 14.2 ohm
|   GND clamp passes 1 mA (typ) near -0.73 V on its own axis
|   POWER clamp passes 1 mA (typ) near -0.62 V on its own axis
|   falling waveform, V_fixture 2.5V, R_fixture 1600Ohm: 20-80 % time 24.3ns typ, 31.8ns min, 19.5ns max; typ from 2.5 V to 0.018 V
|   rising waveform, V_fixture 2.5V, R_fixture 1600Ohm: 20-80 % time 3.38ns typ, 3.36ns min, 3.43ns max; typ from 0.018 V to 2.5 V
|   falling waveform, V_fixture 2.5V, R_fixture 50Ohm: 20-80 % time 94.3ns typ, 134ns min, 59.3ns max; typ from 2.5 V to 0.623 V
|   rising waveform, V_fixture 2.5V, R_fixture 50Ohm: 20-80 % time 318ps typ, 551ps min, 205ps max; typ from 0.622 V to 2.5 V
[Pulldown]
|   Voltage   I(typ)   I(min)   I(max)
-2.5V     -210.3mA   -117.2mA   -348.7mA
-626.4mV  -50.24mA   -27.39mA   -79.98mA
-537.7mV  -43.71mA   -25.04mA   -70.22mA
-248.7mV  -20.92mA   -11.66mA   -34.69mA
197.5mV   15.67mA    8.402mA    26.71mA
412.3mV   28.57mA    15.32mA    48.39mA
649mV     38.55mA    20.56mA    65.11mA
947.6mV   45.69mA    24.09mA    76.8mA
1.396V    49.78mA    26.36mA    81.98mA
2.445V    52.93mA    28.55mA    85.27mA
5V        55.91mA    30.57mA    88.76mA
[GND Clamp]
|   Voltage   I(typ)   I(min)   I(max)
-2.5V     -991.9mA   -800.7mA   -1.23A
-1.244V   -216.8mA   -222.4mA   -217.9mA
-1.133V   -151.8mA   -173.3mA   -134mA
-1.082V   -123.3mA   -151.6mA   -97.87mA
-1.05V    -105.6mA   -137.9mA   -76.05mA
-986.9mV  -71.64mA   -111.1mA   -37.03mA
-931.2mV  -44.36mA   -88.35mA   -13.78mA
-826.8mV  -8.221mA   -48.41mA   -3.55mA
-723.4mV  -761.5uA   -16.63mA   -1.256mA
-641.1mV  -162.4uA   -3.43mA    -345.3uA
-551.8mV  -25.76uA   -320.1uA   -49.4uA
5V        0A         0A         0A
[POWER Clamp]
|   Voltage   I(typ)   I(min)   I(max)
-2.5V     847.2mA    877.1mA    847mA
-1.31V    217.7mA    270.2mA    190mA
-1.167V   146.9mA    201mA      116.8mA
-1.061V   96.59mA    151.1mA    65.69mA
-984.2mV  62.24mA    116mA      33.04mA
-939.6mV  43.85mA    96.26mA    18.54mA
-851.7mV  14.89mA    59.51mA    7.461mA
-782.2mV  4.817mA    33.86mA    5.017mA
-692.8mV  1.973mA    10.24mA    2.675mA
-585mV    642.1uA    1.23mA     806.2uA
-248.7mV  219.5nA    1.335uA    53.34nA
5V        0A         0A         0A
[Ramp]
R_load = 1600
|   typ   min   max
dV/dt_r   1.48929/3.3847e-09   1.39118/3.35752e-09   1.58339/3.43403e-09
dV/dt_f   1.48928/2.43191e-08   1.39117/3.18066e-08   1.58339/1.95368e-08
[Falling Waveform]
V_fixture = 2.5V
V_fixture_min = 2.35V
V_fixture_max = 2.65V
R_fixture = 1600Ohm
|   Time   V(typ)   V(min)   V(max)
0s        2.5V       2.35V      2.65V
18.22ns   2.505V     2.357V     2.596V
25.9ns    2.387V     2.347V     2.084V
36.72ns   1.8V       2.185V     1.202V
49.46ns   1.01V      1.678V     200.1mV
55.48ns   644.4mV    1.41V      59.41mV
64.96ns   153.4mV    983.5mV    31.86mV
81.4ns    49.31mV    291.7mV    20.53mV
93.9ns    36.38mV    109.9mV    17.26mV
398.4ns   17.97mV    31.79mV    11.05mV
[Rising Waveform]
V_fixture = 2.5V
V_fixture_min = 2.35V
V_fixture_max = 2.65V
R_fixture = 1600Ohm
|   Time   V(typ)   V(min)   V(max)
0s        17.85mV    31.36mV    11.02mV
1.709ns   17.98mV    31.36mV    17.16mV
2.508ns   22.07mV    31.55mV    677.6mV
3.223ns   523mV      30.42mV    1.171V
4.237ns   1.191V     53.78mV    1.668V
6.23ns    1.926V     1.248V     2.218V
8.058ns   2.23V      1.834V     2.446V
10ns      2.376V     2.122V     2.554V
13.53ns   2.471V     2.297V     2.627V
36.72ns   2.5V       2.35V      2.65V
[Falling Waveform]
V_fixture = 2.5V
V_fixture_min = 2.35V
V_fixture_max = 2.65V
R_fixture = 50Ohm
|   Time   V(typ)   V(min)   V(max)
0s        2.5V       2.35V      2.65V
21.46ns   2.499V     2.35V      2.617V
44.43ns   2.253V     2.3V       2.025V
88ns      1.57V      1.93V      984.1mV
106.9ns   1.339V     1.79V      720.6mV
135.3ns   1.076V     1.615V     541mV
190.5ns   802.3mV    1.383V     436mV
270.5ns   680.8mV    1.218V     396.4mV
411.8ns   633mV      1.125V     383.6mV
751.8ns   622.7mV    1.098V     380.4mV
[Rising Waveform]
V_fixture = 2.5V
V_fixture_min = 2.35V
V_fixture_max = 2.65V
R_fixture = 50Ohm
|   Time   V(typ)   V(min)   V(max)
0s        622.5mV    1.098V     380.8mV
1.408ns   622.6mV    1.098V     486.3mV
1.522ns   622mV      1.098V     773.7mV
1.772ns   620mV      1.098V     2.349V
1.976ns   650.3mV    1.098V     2.606V
2.262ns   935mV      1.098V     2.645V
2.824ns   2.45V      1.094V     2.65V
3.677ns   2.499V     1.281V     2.65V
4.517ns   2.5V       2.302V     2.65V
5.738ns   2.5V       2.35V      2.65V
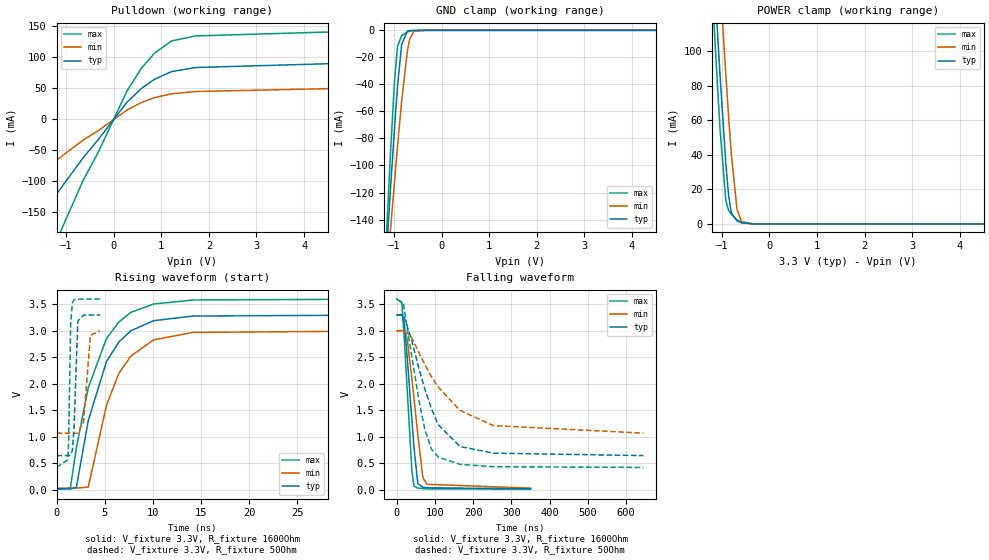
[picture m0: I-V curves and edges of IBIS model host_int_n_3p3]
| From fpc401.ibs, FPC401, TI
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|   host_int_n_3p3 Model
[Model]   host_int_n_3p3
Model_type   I/O_open_drain
Polarity   Non-Inverting
Vinl = 0.8
Vinh = 2
Vmeas = 1.65
Vref = 3.3
Cref = 2pF
Rref = 1600
|   typ   min   max
|   (nom PVT)   (fast PVT)   (slow PVT)
C_comp   1.404e-12   1.340e-12   1.437e-12
| Where nom  PVT is Nominal Process, 3.3V, 27C
|   Fast PVT is Strong Process,  3.6V, -40C
|   Slow PVT is Weak Process,   3V, 125C
[Voltage Range]   3.3   3   3.6
|Junction Temperature
[Temperature Range]   27   125   -40
[Pullup Reference]   3.3   3   3.6
[Pulldown Reference]   0   0   0
[Power Clamp Reference]   3.3   3   3.6
[GND Clamp Reference]   0   0   0
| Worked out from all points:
|   slope of the pulldown table from 0 to 0.495 V, typ, clamps not added: 11.5 ohm
|   GND clamp passes 1 mA (typ) near -0.73 V on its own axis
|   POWER clamp passes 1 mA (typ) near -0.62 V on its own axis
|   falling waveform, V_fixture 3.3V, R_fixture 1600Ohm: 20-80 % time 20.7ns typ, 26.3ns min, 17ns max; typ from 3.3 V to 0.019 V
|   rising waveform, V_fixture 3.3V, R_fixture 1600Ohm: 20-80 % time 3.24ns typ, 3.22ns min, 3.27ns max; typ from 0.019 V to 3.3 V
|   falling waveform, V_fixture 3.3V, R_fixture 50Ohm: 20-80 % time 72.4ns typ, 116ns min, 47.4ns max; typ from 3.3 V to 0.646 V
|   rising waveform, V_fixture 3.3V, R_fixture 50Ohm: 20-80 % time 249ps typ, 443ps min, 170ps max; typ from 0.646 V to 3.3 V
[Pulldown]
|   Voltage   I(typ)   I(min)   I(max)
-3.3V     -339.5mA   -187.8mA   -559.1mA
-632.4mV  -61.24mA   -33.18mA   -96.97mA
-330mV    -33.39mA   -18.81mA   -54.18mA
282mV     27.36mA    14.84mA    45.57mA
580.8mV   49.31mA    26.71mA    81.67mA
858mV     64.18mA    34.58mA    106.1mA
1.214V    76.37mA    40.7mA     125.7mA
1.722V    83.06mA    44.51mA    133.8mA
5.426V    91.13mA    50.52mA    142.2mA
6.6V      95.16mA    52.92mA    148.3mA
[GND Clamp]
|   Voltage   I(typ)   I(min)   I(max)
-3.3V     -1.494A    -1.176A    -1.886A
-1.197V   -188.8mA   -201.3mA   -181.4mA
-1.115V   -141.2mA   -165.3mA   -120.4mA
-1.076V   -119.2mA   -148.5mA   -92.7mA
-985.2mV  -70.38mA   -110.2mA   -35.64mA
-924mV    -40.73mA   -85.2mA    -11.73mA
-838.2mV  -10.43mA   -52.28mA   -3.878mA
-720mV    -701.9uA   -15.68mA   -1.188mA
-672mV    -286.5uA   -6.723mA   -586.3uA
-582mV    -48.43uA   -724.5uA   -97.98uA
-330mV    -82.96nA   -706.3nA   -52.64nA
6.6V      0A         0A         0A
[POWER Clamp]
|   Voltage   I(typ)   I(min)   I(max)
-3.3V     1.287A     1.299A     1.305A
-1.295V   209.6mA    262.4mA    181.5mA
-1.158V   142.2mA    196.3mA    111.8mA
-1.098V   113.5mA    168mA      82.58mA
-1.036V   84.59mA    139mA      53.85mA
-916.8mV  34.87mA    86.14mA    13.38mA
-858mV    16.25mA    61.76mA    7.733mA
-801.9mV  6.387mA    40.47mA    5.615mA
-683.1mV  1.805mA    8.507mA    2.452mA
-588mV    663.9uA    1.288mA    837.5uA
-330mV    2.634uA    8.717uA    1.261uA
6.6V      0A         0A         0A
[Ramp]
R_load = 1600
|   typ   min   max
dV/dt_r   1.96849/3.24241e-09   1.78069/3.22032e-09   2.15251/3.27281e-09
dV/dt_f   1.96847/2.06764e-08   1.78067/2.62986e-08   2.1525/1.69616e-08
[Falling Waveform]
V_fixture = 3.3V
V_fixture_min = 3V
V_fixture_max = 3.6V
R_fixture = 1600Ohm
|   Time   V(typ)   V(min)   V(max)
0s        3.3V       3V         3.6V
13.31ns   3.31V      3.01V      3.541V
19.83ns   3.138V     3V         2.838V
27.04ns   2.52V      2.857V     1.921V
39.45ns   1.332V     2.107V     363mV
45.02ns   800.7mV    1.723V     69.39mV
54.92ns   117.6mV    1.044V     33.59mV
68.24ns   49.6mV     232.8mV    22.85mV
78.82ns   38.62mV    104.2mV    19.26mV
349.9ns   19.34mV    32.71mV    12.54mV
[Rising Waveform]
V_fixture = 3.3V
V_fixture_min = 3V
V_fixture_max = 3.6V
R_fixture = 1600Ohm
|   Time   V(typ)   V(min)   V(max)
0s        19.18mV    32.18mV    12.49mV
1.435ns   16.99mV    32.18mV    33.22mV
2.058ns   46.53mV    32.56mV    791.8mV
3.297ns   1.309V     52.34mV    1.929V
5.189ns   2.421V     1.597V     2.858V
6.463ns   2.788V     2.195V     3.166V
7.728ns   3.003V     2.527V     3.35V
10.09ns   3.192V     2.831V     3.507V
14.15ns   3.279V     2.97V      3.582V
35.47ns   3.3V       3V         3.6V
[Falling Waveform]
V_fixture = 3.3V
V_fixture_min = 3V
V_fixture_max = 3.6V
R_fixture = 50Ohm
|   Time   V(typ)   V(min)   V(max)
0s        3.3V       3V         3.6V
17.28ns   3.295V     3V         3.508V
36.67ns   2.887V     2.902V     2.63V
57.85ns   2.291V     2.59V      1.695V
73.42ns   1.903V     2.362V     1.135V
90.5ns    1.535V     2.138V     769.2mV
108.5ns   1.229V     1.94V      618.1mV
165.3ns   817.4mV    1.499V     480.9mV
252.8ns   691.9mV    1.212V     436.4mV
645.3ns   645.9mV    1.07V      423mV
[Rising Waveform]
V_fixture = 3.3V
V_fixture_min = 3V
V_fixture_max = 3.6V
R_fixture = 50Ohm
|   Time   V(typ)   V(min)   V(max)
0s        646.2mV    1.068V     423.1mV
1.171ns   646.2mV    1.068V     567.9mV
1.25ns    645.5mV    1.068V     862.9mV
1.471ns   658mV      1.068V     3.154V
1.652ns   753.9mV    1.068V     3.534V
1.821ns   1.175V     1.068V     3.584V
2.208ns   3.183V     1.065V     3.598V
2.807ns   3.298V     1.288V     3.6V
3.522ns   3.3V       2.918V     3.6V
4.528ns   3.3V       2.999V     3.6V
